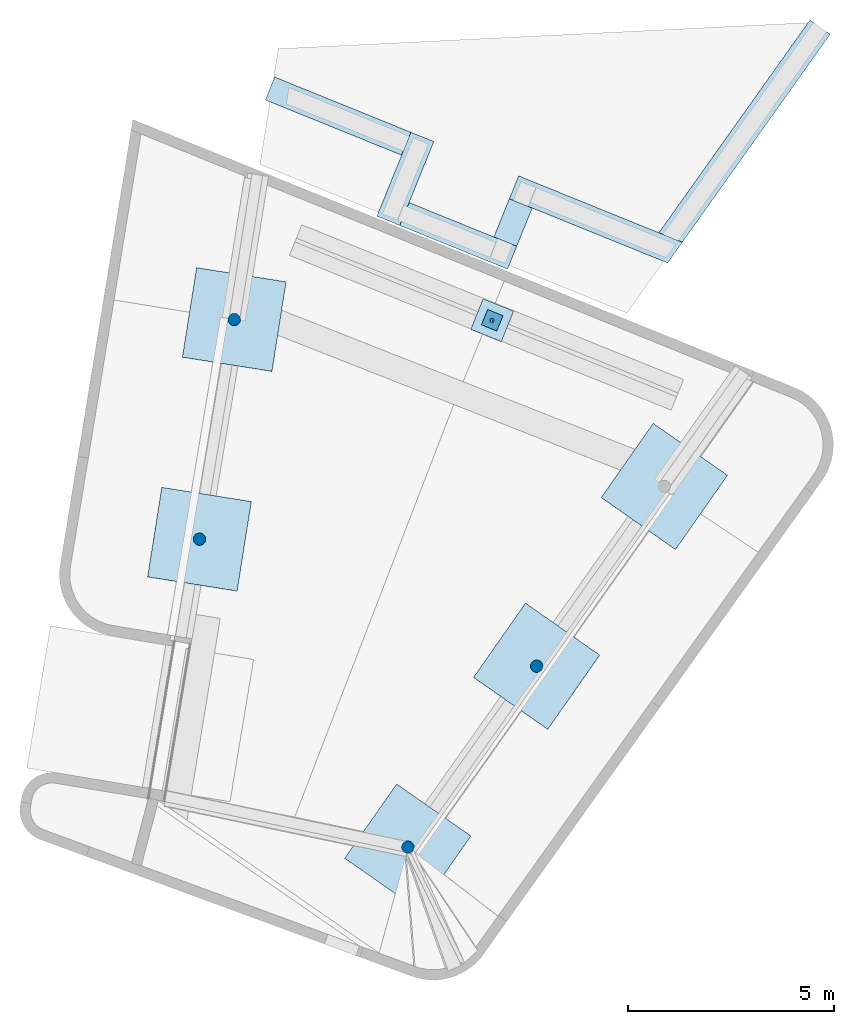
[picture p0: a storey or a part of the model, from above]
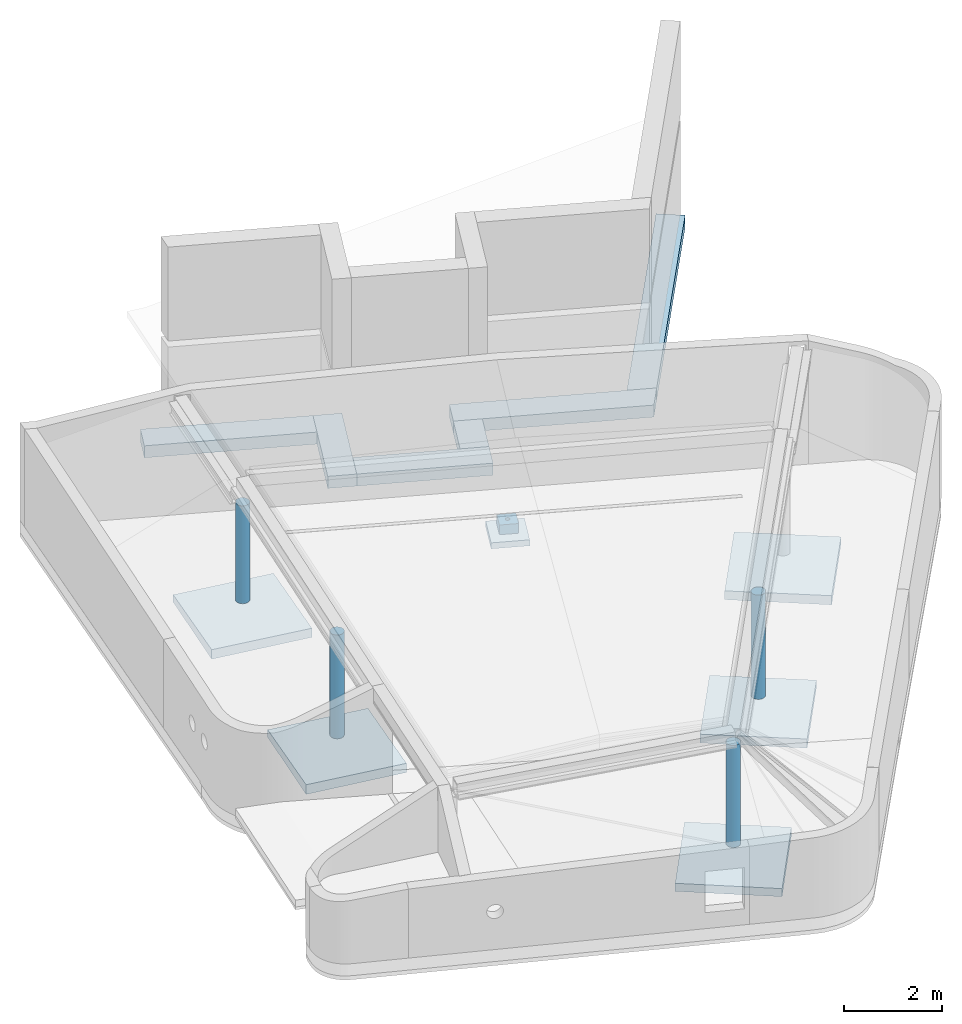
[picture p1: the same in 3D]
Properties of the parts of a building model (IFC2X3), part 1 of 2

# File
Description: ViewDefinition[CoordinationView_V2.0, QuantityTakeOffAddOnView], ExchangeRequirement[Structural, SurfaceGeometry]
File name: CC2.ifc
Time: 2018-02-07T09:57:03
Author: AAJ0\hia
Organization: Structural Designer
Written by: IFC Database Version:Work
Made in: Tekla Structures 2016i Service Pack 6, IFC Export Version: 4.0.0.0 Sep 13 2017

# IfcSite, Site
RefElevation: 0 mm

# IfcBuildingStorey, Undefined
In: Undefined
Elevation: 0 mm

# IfcBeam: 100*100 (2)
In: Undefined
Description: 100*100; Material: CONCRETE/C55/67
Aaj Tagger - Aaj_ObjektStatus: Nytt/ New; sets with these values: 2
Tekla Common - Part mark: Concrete_PLB-1-0(?); Assembly mark: PLB-0(?); Phase: 1; Class: 230; Grade: C55/67; Profile: 100*100; Name: SLUKRENNE; sets with these values: 2
Tekla Quantity - Height: 100 mm; Width: 100 mm; sets with these values: 2
Name | Center of gravity Z (mm) | Center of gravity Y (mm) | Center of gravity X (mm) | Bottom elevation | Top elevation | Net weight (kg) = Gross weight (kg) = Weight (kg) = NetWeight (kg) | Net volume (m3) = Gross volume (m3) | Gross footprint area (m2) | Area per tons (m2) | Net surface area (m2) = Gross area (m2) = OuterSurfaceArea (m2) | Tekla Quantity, Length (mm) = BaseQuantities, Length (mm) | NetVolume (m3)
SLUKRENNE | 36990.3 | 43951.6 | 41374.9 | +36.940 | +37.040 | 83.9938 | 0.035 | 349974 | 16904780 | 1.4199 | 3499.74 | 0.0349974
SLUKRENNE | 36539.9 | 53718.3 | 48906.5 | +36.490 | +36.590 | 240 | 0.1 | 1000000 | 16750000 | 4.02 | 10000 | 0.1

# IfcBeam: 100*800, PLASSTØPTFUNDAMENT
In: Undefined
Description: 100*800; Material: CONCRETE/C45/55
Tekla Common - Center of gravity Z: 36249.9 mm; Center of gravity Y: 53718.3 mm; Center of gravity X: 48906.5 mm; Bottom elevation: +36.200; Top elevation: +36.300; Part mark: Concrete_PLF-1-0(?); Assembly mark: PLF-0(?); Phase: 1; Class: 210; Grade: C45/55; Profile: 100*800; Name: PLASSTØPTFUNDAMENT; sets with these values: 2
Tekla Quantity - Net weight: 1920 kg; Gross weight: 1920 kg; Weight: 1920 kg; Net volume: 0.8 m3; Gross volume: 0.8 m3; Gross footprint area: 7999999 m2; Area per tons: 9458333 m2; Net surface area: 18.16 m2; Gross area: 18.16 m2; Height: 100 mm; Width: 800 mm; Length: 10000 mm; sets with these values: 2
Aaj Tagger - Aaj_ObjektStatus: Nytt/ New; sets with these values: 2
BaseQuantities - Length: 10000 mm; OuterSurfaceArea: 18.16 m2; NetVolume: 0.8 m3; NetWeight: 1920 kg

# IfcBeam: 200*1200, PLASSTØPTFUNDAMENT
In: Undefined
Description: 200*1200; Material: CONCRETE/C45/55
Tekla Common - Center of gravity Z: 36450 mm; Center of gravity Y: 43942.7 mm; Center of gravity X: 41428.1 mm; Bottom elevation: +36.350; Top elevation: +36.550; Part mark: Concrete_PLF-1-0(?); Assembly mark: PLF-0(?); Phase: 1; Class: 210; Grade: C45/55; Profile: 200*1200; Name: PLASSTØPTFUNDAMENT; sets with these values: 2
Tekla Quantity - Net weight: 2995.71 kg; Gross weight: 2995.71 kg; Weight: 2995.71 kg; Net volume: 1.24821 m3; Gross volume: 1.24821 m3; Gross footprint area: 6241064 m2; Area per tons: 5021340 m2; Net surface area: 15.0425 m2; Gross area: 15.0425 m2; Height: 200 mm; Width: 1200 mm; Length: 5200.89 mm; sets with these values: 2
Aaj Tagger - Aaj_Undersortering: BJELKE; Aaj_ObjektStatus: Nytt/ New; sets with these values: 2
BaseQuantities - Length: 5200.89 mm; OuterSurfaceArea: 15.0425 m2; NetVolume: 1.24821 m3; NetWeight: 2995.71 kg

# IfcBeam: HSQ305*6-30*250-15*550 (2)
In: Undefined
Description: HSQ305*6-30*250-15*550; Material: STEEL/S355
Aaj Tagger - Aaj_ObjektStatus: Nytt/ New; sets with these values: 2
Tekla Common - Center of gravity Z: 39252.6 mm; Bottom elevation: +39.100; Top elevation: +39.420; Phase: 1; Class: 330; Grade: S355; Profile: HSQ305*6-30*250-15*550; Name: STÅLBJELKE; sets with these values: 2
Tekla Quantity - Height: 320 mm; Width: 550 mm; sets with these values: 2
Name | Center of gravity Y (mm) | Center of gravity X (mm) | Part mark | Assembly mark | Net weight (kg) = Gross weight (kg) = Weight (kg) = NetWeight (kg) | Net volume (m3) = Gross volume (m3) | Gross footprint area (m2) | Area per tons (m2) | Net surface area (m2) = Gross area (m2) = OuterSurfaceArea (m2) | Tekla Quantity, Length (mm) = BaseQuantities, Length (mm) | NetVolume (m3)
STÅLBJELKE | 51008.8 | 54187.5 | DSB-3(?) | SB-3(?) | 515.938 | 0.06572 | 887164 | 18386113 | 9.4861 | 3386.12 | 0.0657246
STÅLBJELKE | 55426.6 | 43063.1 | DSB-1(?) | SB-1(?) | 542.542 | 0.06911 | 932909 | 18382423 | 9.97323 | 3560.72 | 0.0691136

# IfcBeam: HSQ305*6-40*250-20*390-12, STÅLBJELKE
In: Undefined
Description: HSQ305*6-40*250-20*390-12; Material: STEEL/S355
Aaj Tagger - Aaj_ObjektStatus: Nytt/ New; sets with these values: 2
Tekla Common - Center of gravity Z: 39575.2 mm; Center of gravity Y: 41457.4 mm; Center of gravity X: 44056.4 mm; Bottom elevation: +39.400; Top elevation: +39.725; Part mark: DSB-5(?); Assembly mark: SB-5(?); Phase: 1; Class: 330; Grade: S355; Profile: HSQ305*6-40*250-20*390-12; Name: STÅLBJELKE; sets with these values: 2
Tekla Quantity - Net weight: 1010.7 kg; Gross weight: 1010.7 kg; Weight: 1010.7 kg; Net volume: 0.12875 m3; Gross volume: 0.12875 m3; Gross footprint area: 1571900 m2; Area per tons: 14645252 m2; Net surface area: 14.802 m2; Gross area: 14.802 m2; Height: 325 mm; Width: 390 mm; Length: 5999.62 mm; sets with these values: 2
BaseQuantities - Length: 5999.62 mm; OuterSurfaceArea: 14.802 m2; NetVolume: 0.128752 m3; NetWeight: 1010.7 kg

# IfcBeam: HSQ305*6-40*250-20*550 (2)
In: Undefined
Description: HSQ305*6-40*250-20*550; Material: STEEL/S355
Aaj Tagger - Aaj_ObjektStatus: Nytt/ New; sets with these values: 2
Tekla Common - Center of gravity Z: 39553.7 mm; Bottom elevation: +39.400; Top elevation: +39.725; Phase: 1; Class: 330; Grade: S355; Profile: HSQ305*6-40*250-20*550; Name: STÅLBJELKE; sets with these values: 2
Tekla Quantity - Height: 325 mm; Width: 550 mm; sets with these values: 2
Name | Center of gravity Y (mm) | Center of gravity X (mm) | Part mark | Assembly mark | Net weight (kg) = Gross weight (kg) = Weight (kg) = NetWeight (kg) | Net volume (m3) = Gross volume (m3) | Gross footprint area (m2) | Area per tons (m2) | Net surface area (m2) = Gross area (m2) | Tekla Quantity, Length (mm) = BaseQuantities, Length (mm) | OuterSurfaceArea (m2) | NetVolume (m3)
STÅLBJELKE | 45244.7 | 50100.8 | DSB-4(?) | SB-4(?) | 2080.12 | 0.26498 | 2815309 | 14384624 | 29.9217 | 10745.5 | 29.9217 | 0.264983
STÅLBJELKE | 49752.5 | 42124.7 | DSB-2(?) | SB-2(?) | 1537.38 | 0.19584 | 2080745 | 14392994 | 22.1274 | 7941.77 | 22.1275 | 0.195844

# IfcBeam: HSQ305*6-40*250-25*390-15, STÅLBJELKE
In: Undefined
Description: HSQ305*6-40*250-25*390-15; Material: STEEL/S355
Aaj Tagger - Aaj_ObjektStatus: Nytt/ New; sets with these values: 2
Tekla Common - Center of gravity Z: 39565.4 mm; Center of gravity Y: 43922.1 mm; Center of gravity X: 41169.1 mm; Bottom elevation: +39.400; Top elevation: +39.730; Part mark: DSB-6(?); Assembly mark: SB-6(?); Phase: 1; Class: 330; Grade: S355; Profile: HSQ305*6-40*250-25*390-15; Name: STÅLBJELKE; sets with these values: 2
Tekla Quantity - Net weight: 712.152 kg; Gross weight: 712.152 kg; Weight: 712.152 kg; Net volume: 0.09072 m3; Gross volume: 0.09072 m3; Gross footprint area: 1015319 m2; Area per tons: 13506568 m2; Net surface area: 9.61873 m2; Gross area: 9.61873 m2; Height: 330 mm; Width: 390 mm; Length: 3875.27 mm; sets with these values: 2
BaseQuantities - Length: 3875.27 mm; OuterSurfaceArea: 9.61873 m2; NetVolume: 0.09072 m3; NetWeight: 712.152 kg

# IfcBeam: RHS100*4, STÅLBJELKE
In: Undefined
Description: RHS100*4; Material: STEEL/S355
Aaj Tagger - Aaj_ObjektStatus: Nytt/ New; sets with these values: 2
Tekla Common - Center of gravity Z: 39470 mm; Center of gravity Y: 49785.7 mm; Center of gravity X: 41927.3 mm; Bottom elevation: +39.420; Top elevation: +39.520; Part mark: DSB-8(?); Assembly mark: SB-8(?); Phase: 1; Class: 330; Grade: S355; Profile: RHS100*4; Name: STÅLBJELKE; sets with these values: 2
Tekla Quantity - Net weight: 95.7589 kg; Gross weight: 95.3849 kg; Weight: 95.3849 kg; Net volume: 0.0122 m3; Gross volume: 0.01215 m3; Gross footprint area: 794179 m2; Area per tons: 32554848 m2; Net surface area: 3.17832 m2; Gross area: 3.10524 m2; Height: 100 mm; Width: 100 mm; Length: 7941.79 mm; sets with these values: 2
BaseQuantities - Length: 7941.79 mm; OuterSurfaceArea: 3.10524 m2; NetVolume: 0.0121986 m3; NetWeight: 95.7589 kg

# IfcBeam: RHS100*5 (4)
In: Undefined
Description: RHS100*5; Material: STEEL/S355
Aaj Tagger - Aaj_ObjektStatus: Nytt/ New; sets with these values: 2
Tekla Common - Phase: 1; Class: 330; Grade: S355; Profile: RHS100*5; Name: STÅLBJELKE; sets with these values: 2
Tekla Quantity - Area per tons: 26219122 m2; Height: 100 mm; Width: 100 mm; sets with these values: 2
Name | Center of gravity Z (mm) | Center of gravity Y (mm) | Center of gravity X (mm) | Bottom elevation | Top elevation | Part mark | Assembly mark | Net weight (kg) = NetWeight (kg) | Gross weight (kg) = Weight (kg) | Net volume (m3) | Gross volume (m3) | Gross footprint area (m2) | Net surface area (m2) | Gross area (m2) = OuterSurfaceArea (m2) | Tekla Quantity, Length (mm) = BaseQuantities, Length (mm) | NetVolume (m3)
STÅLBJELKE | 39470 | 45140.1 | 50248.5 | +39.420 | +39.520 | DSB-0(?) | SB-0(?) | 160.268 | 159.425 | 0.02042 | 0.02031 | 1074546 | 4.30018 | 4.17998 | 10745.5 | 0.0204164
STÅLBJELKE | 39165 | 50857.4 | 54301.7 | +39.115 | +39.215 | DSB-0(?) | SB-0(?) | 48.8032 | 48.5464 | 0.00622 | 0.00618 | 327209 | 1.31084 | 1.27284 | 3272.09 | 0.00621697
STÅLBJELKE | 39165 | 55455 | 42884.3 | +39.115 | +39.215 | DSB-0(?) | SB-0(?) | 53.1082 | 52.8287 | 0.00677 | 0.00673 | 356072 | 1.42629 | 1.38512 | 3560.72 | 0.00676537
STÅLBJELKE | 39470 | 41298.8 | 44023.1 | +39.420 | +39.520 | DSB-7(?) | SB-7(?) | 89.4844 | 89.0134 | 0.0114 | 0.01134 | 599962 | 2.40185 | 2.33385 | 5999.62 | 0.0113993

# IfcBeam: TRIANGLE300*600, PLASSTØPTBJELKE
In: Undefined
Description: TRIANGLE300*600; Material: CONCRETE/C55/67
Aaj Tagger - Aaj_ObjektStatus: Nytt/ New; sets with these values: 2
Tekla Common - Center of gravity Z: 39540 mm; Center of gravity Y: 51837.8 mm; Center of gravity X: 48063.4 mm; Bottom elevation: +39.440; Top elevation: +39.740; Part mark: Concrete_PLB-1-0(?); Assembly mark: PLB-0(?); Phase: 1; Class: 230; Grade: C55/67; Profile: TRIANGLE300*600; Name: PLASSTØPTBJELKE; sets with these values: 2
Tekla Quantity - Net weight: 2348.64 kg; Gross weight: 2348.64 kg; Weight: 2348.64 kg; Net volume: 0.9786 m3; Gross volume: 0.9786 m3; Gross footprint area: 0 m2; Area per tons: 7348957 m2; Net surface area: 17.26 m2; Gross area: 17.26 m2; Height: 300 mm; Width: 600 mm; Length: 10873.3 mm; sets with these values: 2
BaseQuantities - Length: 10873.3 mm; OuterSurfaceArea: 17.26 m2; NetVolume: 0.978599 m3; NetWeight: 2348.64 kg

# IfcColumn: D300 (5)
In: Undefined
Description: D300; Material: CONCRETE/C55/67
Aaj Tagger - Aaj_ObjektStatus: Nytt/ New; sets with these values: 2
Tekla Common - Part mark: Concrete_PLS-1-3(?); Assembly mark: PLS-0(?); Phase: 1; Class: 220; Grade: C55/67; Profile: D300; Name: PLASSTØPTSØYLE; sets with these values: 2
Tekla Quantity - Gross footprint area: 70232.5 m2; Height: 300 mm; Width: 300 mm; sets with these values: 2
Name | Center of gravity Z (mm) | Center of gravity Y (mm) | Center of gravity X (mm) | Bottom elevation | Top elevation | Net weight (kg) = Gross weight (kg) = Weight (kg) | Net volume (m3) = Gross volume (m3) | Area per tons (m2) | Net surface area (m2) = Gross area (m2) = OuterSurfaceArea (m2) | Tekla Quantity, Length (mm) = BaseQuantities, Length (mm) | NetVolume (m3) | NetWeight (kg)
PLASSTØPTSØYLE | 38103.4 | 48334.8 | 41938.7 | +36.807 | +39.400 | 437.089 | 0.18212 | 5903801 | 2.58049 | 2593.11 | 0.18212 | 437.089
PLASSTØPTSØYLE | 37876.3 | 53668.3 | 42783.5 | +36.653 | +39.100 | 412.517 | 0.17188 | 5922944 | 2.44331 | 2447.33 | 0.171882 | 412.516
PLASSTØPTSØYLE | 37873.5 | 49616.1 | 53224.5 | +36.647 | +39.100 | 413.477 | 0.17228 | 5922153 | 2.44868 | 2453.03 | 0.172282 | 413.477
PLASSTØPTSØYLE | 38097.6 | 45251.2 | 50123.7 | +36.795 | +39.400 | 439.063 | 0.18294 | 5902357 | 2.59151 | 2604.82 | 0.182943 | 439.063
PLASSTØPTSØYLE | 38125 | 40859.8 | 46996.1 | +36.850 | +39.400 | 429.823 | 0.17909 | 5909234 | 2.53992 | 2550 | 0.179093 | 429.823

# IfcFooting: 2200*2200 (5)
In: Undefined
Description: 2200*2200; Material: CONCRETE/C45/55
Tekla Common - Part mark: Concrete_PLF-1-19(?); Assembly mark: PLF-0(?); Phase: 1; Class: 210; Grade: C45/55; Profile: 2200*2200; Name: PLASSTØPTFUNDAMENT; sets with these values: 2
Tekla Quantity - Height: 2200 mm; Width: 2200 mm; sets with these values: 2
Aaj Tagger - Aaj_Undersortering: PUNKT; Aaj_ObjektStatus: Nytt/ New; sets with these values: 2
BaseQuantities - CrossSectionArea: 4.84 m2; Width: 2200 mm; Height: 2200 mm
Name | Center of gravity Z (mm) | Center of gravity Y (mm) | Center of gravity X (mm) | Bottom elevation | Top elevation | Net weight (kg) = Weight (kg) = NetWeight (kg) | Gross weight (kg) = GrossWeight (kg) | Net volume (m3) | Gross volume (m3) = GrossVolume (m3) | Gross footprint area (m2) | Area per tons (m2) | Net surface area (m2) = OuterSurfaceArea (m2) | Gross area (m2) = GrossSurfaceArea (m2) | Tekla Quantity, Length (mm) = BaseQuantities, Length (mm) | NetVolume (m3)
PLASSTØPTFUNDAMENT | 36404.9 | 48293.4 | 41920.9 | +36.293 | +36.546 | 2419.97 | 2775.32 | 1.00832 | 1.20992 | 0 | 4757766 | 11.5137 | 11.8799 | 238.922 | 1.00832
PLASSTØPTFUNDAMENT | 36253.2 | 53624.4 | 42765.7 | +36.143 | +36.393 | 2378.67 | 2740.99 | 0.99111 | 1.20992 | 0 | 4827637 | 11.4834 | 11.8799 | 235.966 | 0.991114
PLASSTØPTFUNDAMENT | 36249.8 | 49572.8 | 53205.6 | +36.143 | +36.385 | 2300.02 | 2642.24 | 0.95834 | 1.20992 | 0 | 4966780 | 11.4237 | 11.8799 | 227.465 | 0.958341
PLASSTØPTFUNDAMENT | 36450 | 40859.8 | 46996.1 | +36.350 | +36.550 | 2323.2 | 2323.2 | 0.968 | 0.968 | 4840000 | 4924242 | 11.44 | 11.44 | 200 | 0.968
PLASSTØPTFUNDAMENT | 36399.2 | 45207.8 | 50104.7 | +36.293 | +36.534 | 2286.67 | 2628.88 | 0.95278 | 1.20992 | 0 | 4991359 | 11.4136 | 11.8799 | 226.316 | 0.952778

# IfcFooting: 300*600 (6)
In: Undefined
Description: 300*600; Material: CONCRETE/B35
Tekla Common - Center of gravity Z: 36850 mm; Bottom elevation: +36.700; Top elevation: +37.000; Assembly mark: PLF-2; Phase: 1; Class: 210; Grade: B35; Profile: 300*600; Name: PLASSTØPTFUNDAMENT; sets with these values: 2
Tekla Quantity - Height: 300 mm; Width: 600 mm; sets with these values: 2
Aaj Tagger - Aaj_Undersortering: STRIPE; Aaj_ObjektStatus: Eksisterende/ Existing; sets with these values: 2
BaseQuantities - CrossSectionArea: 0.18 m2; Width: 600 mm; Height: 300 mm
Name | Center of gravity Y (mm) | Center of gravity X (mm) | Part mark | Net weight (kg) = Weight (kg) = NetWeight (kg) | Gross weight (kg) = GrossWeight (kg) | Net volume (m3) = Gross volume (m3) | Gross footprint area (m2) | Area per tons (m2) | Net surface area (m2) = Gross area (m2) = OuterSurfaceArea (m2) = GrossSurfaceArea (m2) | Tekla Quantity, Length (mm) = BaseQuantities, Length (mm) | NetVolume (m3) = GrossVolume (m3)
PLASSTØPTFUNDAMENT | 56022.9 | 49551 | Concrete_PLF-1-6 | 432.04 | 432.1 | 0.18002 | 600056 | 4999923 | 2.16017 | 1000.23 | 0.180017
PLASSTØPTFUNDAMENT | 55698.5 | 48221.9 | Concrete_PLF-1-5 | 1218.32 | 1218.41 | 0.50764 | 1692117 | 4462155 | 5.43635 | 2820.39 | 0.507635
PLASSTØPTFUNDAMENT | 57081.7 | 46937.1 | Concrete_PLF-1-4 | 949.61 | 949.7 | 0.39567 | 1318903 | 4545770 | 4.31671 | 2198.38 | 0.395671
PLASSTØPTFUNDAMENT | 58605.9 | 45305.1 | Concrete_PLF-1-3 | 1542.18 | 1542.23 | 0.64258 | 2141919 | 4400102 | 6.78576 | 3569.98 | 0.642576
PLASSTØPTFUNDAMENT | 58213.1 | 55189.6 | Concrete_PLF-1-2 | 2706.08 | 2736.81 | 1.12754 | 3758451 | 4301544 | 11.6403 | 6335.2 | 1.12754
PLASSTØPTFUNDAMENT | 56086.2 | 51529.2 | Concrete_PLF-1-7 | 1822.63 | 1853.37 | 0.75943 | 2531426 | 4366921 | 7.95927 | 4290.2 | 0.759428

# IfcFooting: 400*400, OLJEUTSKILLER
In: Undefined
Description: 400*400; Material: CONCRETE/C45/55
Tekla Common - Center of gravity Z: 36368.2 mm; Center of gravity Y: 53649.1 mm; Center of gravity X: 49044.3 mm; Bottom elevation: +36.249; Top elevation: +36.492; Part mark: Concrete_PLF-1-1(?); Assembly mark: PLF-0(?); Phase: 1; Class: 210; Grade: C45/55; Profile: 400*400; Name: OLJEUTSKILLER; sets with these values: 2
Tekla Quantity - Net weight: 86.3647 kg; Gross weight: 92.6545 kg; Weight: 86.3647 kg; Net volume: 0.03599 m3; Gross volume: 0.04 m3; Gross footprint area: 0 m2; Area per tons: 8850370 m2; Net surface area: 0.76436 m2; Gross area: 0.71997 m2; Height: 400 mm; Width: 400 mm; Length: 241.288 mm; sets with these values: 2
Aaj Tagger - Aaj_Undersortering: PUNKT; Aaj_Delmengde: OLJEUTSKILLER; Aaj_ObjektStatus: Nytt/ New; sets with these values: 2
BaseQuantities - Length: 241.288 mm; OuterSurfaceArea: 0.76436 m2; GrossSurfaceArea: 0.719974 m2; CrossSectionArea: 0.16 m2; NetVolume: 0.0359853 m3; GrossVolume: 0.0399974 m3; NetWeight: 86.3647 kg; GrossWeight: 92.6545 kg; Width: 400 mm; Height: 400 mm

# IfcFooting: 800*800, PLASSTØPTFUNDAMENT
In: Undefined
Description: 800*800; Material: CONCRETE/C45/55
Aaj Tagger - Aaj_Undersortering: PUNKT; Aaj_Delmengde: OLJEUTSKILLER; Aaj_ObjektStatus: Nytt/ New; sets with these values: 2
Tekla Common - Center of gravity Z: 36126 mm; Center of gravity Y: 53650.5 mm; Center of gravity X: 49044.7 mm; Bottom elevation: +36.048; Top elevation: +36.204; Part mark: Concrete_PLF-1-1(?); Assembly mark: PLF-0(?); Phase: 1; Class: 210; Grade: C45/55; Profile: 800*800; Name: PLASSTØPTFUNDAMENT; sets with these values: 2
Tekla Quantity - Net weight: 227.2 kg; Gross weight: 227.2 kg; Weight: 227.2 kg; Net volume: 0.09467 m3; Gross volume: 0.09467 m3; Gross footprint area: 0 m2; Area per tons: 7717138 m2; Net surface area: 1.75333 m2; Gross area: 1.75333 m2; Height: 800 mm; Width: 800 mm; Length: 147.917 mm; sets with these values: 2
BaseQuantities - Length: 147.917 mm; OuterSurfaceArea: 1.75333 m2; GrossSurfaceArea: 1.75333 m2; CrossSectionArea: 0.64 m2; NetVolume: 0.0946666 m3; GrossVolume: 0.0946666 m3; NetWeight: 227.2 kg; GrossWeight: 227.2 kg; Width: 800 mm; Height: 800 mm

# IfcPlate: 0.5*2664, MEMBRAN
In: Undefined
Description: 0.5*2664; Material: MISCELLANEOUS/Misc_Undefined
Aaj Tagger - Aaj_ObjektStatus: Nytt/ New; sets with these values: 2
Tekla Common - Center of gravity Z: 38973.5 mm; Center of gravity Y: 50118.3 mm; Center of gravity X: 55433.2 mm; Bottom elevation: +38.504; Top elevation: +39.422; Part mark: Concrete_IXPS-1-0(?); Assembly mark: IXPS-0(?); Phase: 1; Class: 912; Grade: Misc_Undefined; Profile: 0.5*2664; Name: MEMBRAN; sets with these values: 2
Tekla Quantity - Net weight: 0 kg; Gross weight: 0 kg; Weight: 0 kg; Net volume: 0.00453 m3; Gross volume: 0.00496 m3; Gross footprint area: 0 m2; Net surface area: 18.1338 m2; Gross area: 9.68366 m2; Height: 2663.91 mm; Width: 0.5 mm; Length: 3635.14 mm; sets with these values: 2
BaseQuantities - Width: 2663.91 mm; NetArea: 18.1338 m2; GrossArea: 9.68366 m2; CrossSectionArea: 2.5e-07 m2; NetVolume: 0.00453197 m3; GrossVolume: 0.00495974 m3

# IfcPlate: 0.5*2751, MEMBRAN
In: Undefined
Description: 0.5*2751; Material: MISCELLANEOUS/Misc_Undefined
Aaj Tagger - Aaj_ObjektStatus: Nytt/ New; sets with these values: 2
Tekla Common - Center of gravity Z: 39126.1 mm; Center of gravity Y: 44341.7 mm; Center of gravity X: 51368.5 mm; Bottom elevation: +38.524; Top elevation: +39.720; Part mark: Concrete_IXPS-1-0(?); Assembly mark: IXPS-0(?); Phase: 1; Class: 912; Grade: Misc_Undefined; Profile: 0.5*2751; Name: MEMBRAN; sets with these values: 2
Tekla Quantity - Net weight: 0 kg; Gross weight: 0 kg; Weight: 0 kg; Net volume: 0.01471 m3; Gross volume: 0.01526 m3; Gross footprint area: 0 m2; Net surface area: 58.8691 m2; Gross area: 29.8807 m2; Height: 2750.94 mm; Width: 0.5 mm; Length: 10862 mm; sets with these values: 2
BaseQuantities - Width: 2750.94 mm; NetArea: 58.8691 m2; GrossArea: 29.8808 m2; CrossSectionArea: 2.5e-07 m2; NetVolume: 0.0147137 m3; GrossVolume: 0.0152558 m3

# IfcPlate: 0.5*2815, MEMBRAN
In: Undefined
Description: 0.5*2815; Material: MISCELLANEOUS/Misc_Undefined
Aaj Tagger - Aaj_ObjektStatus: Nytt/ New; sets with these values: 2
Tekla Common - Center of gravity Z: 38944 mm; Center of gravity Y: 55804 mm; Center of gravity X: 41442.6 mm; Bottom elevation: +38.495; Top elevation: +39.415; Part mark: Concrete_IXPS-1-0(?); Assembly mark: IXPS-0(?); Phase: 1; Class: 912; Grade: Misc_Undefined; Profile: 0.5*2815; Name: MEMBRAN; sets with these values: 2
Tekla Quantity - Net weight: 0 kg; Gross weight: 0 kg; Weight: 0 kg; Net volume: 0.00531 m3; Gross volume: 0.00574 m3; Gross footprint area: 0 m2; Net surface area: 21.252 m2; Gross area: 11.5174 m2; Height: 2814.62 mm; Width: 0.5 mm; Length: 4092 mm; sets with these values: 2
BaseQuantities - Width: 2814.62 mm; NetArea: 21.252 m2; GrossArea: 11.5174 m2; CrossSectionArea: 2.5e-07 m2; NetVolume: 0.00531136 m3; GrossVolume: 0.00573829 m3

# IfcPlate: 0.5*2953, MEMBRAN
In: Undefined
Description: 0.5*2953; Material: MISCELLANEOUS/Misc_Undefined
Aaj Tagger - Aaj_ObjektStatus: Nytt/ New; sets with these values: 2
Tekla Common - Center of gravity Z: 39117.5 mm; Center of gravity Y: 50134.2 mm; Center of gravity X: 40514.8 mm; Bottom elevation: +38.493; Top elevation: +39.726; Part mark: Concrete_IXPS-1-0(?); Assembly mark: IXPS-0(?); Phase: 1; Class: 912; Grade: Misc_Undefined; Profile: 0.5*2953; Name: MEMBRAN; sets with these values: 2
Tekla Quantity - Net weight: 0 kg; Gross weight: 0 kg; Weight: 0 kg; Net volume: 0.01128 m3; Gross volume: 0.01155 m3; Gross footprint area: 0 m2; Net surface area: 45.1327 m2; Gross area: 23.0887 m2; Height: 2952.85 mm; Width: 0.5 mm; Length: 7819.12 mm; sets with these values: 2
BaseQuantities - Width: 2952.85 mm; NetArea: 45.1327 m2; GrossArea: 23.0887 m2; CrossSectionArea: 2.5e-07 m2; NetVolume: 0.0112806 m3; GrossVolume: 0.0115528 m3

# IfcPlate: 0.5*3189, MEMBRAN
In: Undefined
Description: 0.5*3189; Material: MISCELLANEOUS/Misc_Undefined
Aaj Tagger - Aaj_ObjektStatus: Nytt/ New; sets with these values: 2
Tekla Common - Center of gravity Z: 39514.2 mm; Center of gravity Y: 52178.1 mm; Center of gravity X: 51403.6 mm; Bottom elevation: +39.440; Top elevation: +39.591; Part mark: Concrete_IXPS-1-4(?); Assembly mark: IXPS-4(?); Phase: 1; Class: 912; Grade: Misc_Undefined; Profile: 0.5*3189; Name: MEMBRAN; sets with these values: 2
Tekla Quantity - Net weight: 0 kg; Gross weight: 0 kg; Weight: 0 kg; Net volume: 0.00856 m3; Gross volume: 0.00912 m3; Gross footprint area: 0 m2; Net surface area: 34.2758 m2; Gross area: 19.3506 m2; Height: 3189.15 mm; Width: 150.5 mm; Length: 6067.64 mm; sets with these values: 2
BaseQuantities - Width: 3189.15 mm; NetArea: 34.2758 m2; GrossArea: 19.3506 m2; CrossSectionArea: 2.5e-07 m2; NetVolume: 0.0085634 m3; GrossVolume: 0.00912207 m3

# IfcPlate: 0.5*3290, MEMBRAN
In: Undefined
Description: 0.5*3290; Material: MISCELLANEOUS/Misc_Undefined
Aaj Tagger - Aaj_ObjektStatus: Nytt/ New; sets with these values: 2
Tekla Common - Center of gravity Z: 39517.2 mm; Center of gravity Y: 54333.9 mm; Center of gravity X: 46005.7 mm; Bottom elevation: +39.440; Top elevation: +39.591; Part mark: Concrete_IXPS-1-6(?); Assembly mark: IXPS-6(?); Phase: 1; Class: 912; Grade: Misc_Undefined; Profile: 0.5*3290; Name: MEMBRAN; sets with these values: 2
Tekla Quantity - Net weight: 0 kg; Gross weight: 0 kg; Weight: 0 kg; Net volume: 0.00914 m3; Gross volume: 0.00972 m3; Gross footprint area: 0 m2; Net surface area: 36.5751 m2; Gross area: 20.8552 m2; Height: 3290.31 mm; Width: 150.5 mm; Length: 6338.36 mm; sets with these values: 2
BaseQuantities - Width: 3290.31 mm; NetArea: 36.5751 m2; GrossArea: 20.8552 m2; CrossSectionArea: 2.5e-07 m2; NetVolume: 0.00913822 m3; GrossVolume: 0.00971979 m3

# IfcPlate: 0.5*5306, MEMBRAN
In: Undefined
Description: 0.5*5306; Material: MISCELLANEOUS/Misc_Undefined
Aaj Tagger - Aaj_ObjektStatus: Nytt/ New; sets with these values: 2
Tekla Common - Center of gravity Z: 39815.3 mm; Center of gravity Y: 45985.2 mm; Center of gravity X: 48093 mm; Bottom elevation: +39.740; Top elevation: +39.890; Part mark: Concrete_IXPS-1-5(?); Assembly mark: IXPS-5(?); Phase: 1; Class: 912; Grade: Misc_Undefined; Profile: 0.5*5306; Name: MEMBRAN; sets with these values: 2
Tekla Quantity - Net weight: 0 kg; Gross weight: 0 kg; Weight: 0 kg; Net volume: 0.71928 m3; Gross volume: 0.71928 m3; Gross footprint area: 0 m2; Net surface area: 83.6087 m2; Gross area: 56.9467 m2; Height: 5305.71 mm; Width: 150.5 mm; Length: 10733.1 mm; sets with these values: 2
BaseQuantities - Width: 5305.71 mm; NetArea: 83.6087 m2; GrossArea: 56.9467 m2; CrossSectionArea: 2.5e-07 m2; NetVolume: 0.719278 m3; GrossVolume: 0.719278 m3

# IfcPlate: 0.5*5446, MEMBRAN
In: Undefined
Description: 0.5*5446; Material: MISCELLANEOUS/Misc_Undefined
Aaj Tagger - Aaj_ObjektStatus: Nytt/ New; sets with these values: 2
Tekla Common - Center of gravity Z: 39808.1 mm; Center of gravity Y: 47730.4 mm; Center of gravity X: 44178.2 mm; Bottom elevation: +39.740; Top elevation: +39.890; Part mark: Concrete_IXPS-1-5(?); Assembly mark: IXPS-0(?); Phase: 1; Class: 912; Grade: Misc_Undefined; Profile: 0.5*5446; Name: MEMBRAN; sets with these values: 2
Tekla Quantity - Net weight: 0 kg; Gross weight: 0 kg; Weight: 0 kg; Net volume: 0.02446 m3; Gross volume: 0.02446 m3; Gross footprint area: 0 m2; Net surface area: 97.8982 m2; Gross area: 63.5609 m2; Height: 5446.06 mm; Width: 150.5 mm; Length: 11671 mm; sets with these values: 2
BaseQuantities - Width: 5446.06 mm; NetArea: 97.8982 m2; GrossArea: 63.5609 m2; CrossSectionArea: 2.5e-07 m2; NetVolume: 0.0244554 m3; GrossVolume: 0.0244554 m3

# IfcPlate: 100*10545, ISOLASJON
In: Undefined
Description: 100*10545; Material: MISCELLANEOUS/XPS
Aaj Tagger - Aaj_ObjektStatus: Nytt/ New; sets with these values: 2
Tekla Common - Center of gravity Z: 36341.8 mm; Center of gravity Y: 50311.5 mm; Center of gravity X: 47405.4 mm; Bottom elevation: +36.150; Top elevation: +36.550; Part mark: Concrete_PLD-1-0(?); Assembly mark: PLD-0(?); Phase: 1; Class: 912; Grade: XPS; Profile: 100*10545; Name: ISOLASJON; sets with these values: 2
Tekla Quantity - Net weight: 431.282 kg; Gross weight: 496.509 kg; Weight: 431.282 kg; Net volume: 17.2513 m3; Gross volume: 17.2513 m3; Gross footprint area: 0 m2; Area per tons: 818902108 m2; Net surface area: 353.178 m2; Gross area: 198.604 m2; Height: 10545.4 mm; Width: 400 mm; Length: 18833.2 mm; sets with these values: 2
BaseQuantities - Width: 10545.4 mm; NetArea: 353.178 m2; GrossArea: 198.604 m2; CrossSectionArea: 0.01 m2; NetVolume: 17.2513 m3; GrossVolume: 17.2513 m3

# IfcPlate: 100*3237, VEKSTLAG
In: Undefined
Description: 100*3237; Material: MISCELLANEOUS/Misc_Undefined
Aaj Tagger - Aaj_ObjektStatus: Nytt/ New; sets with these values: 2
Tekla Common - Center of gravity Z: 39663.5 mm; Center of gravity Y: 52083.1 mm; Center of gravity X: 51372.4 mm; Bottom elevation: +39.540; Top elevation: +39.790; Part mark: Concrete_IXPS-1-4(?); Assembly mark: IXPS-0(?); Phase: 1; Class: 911; Grade: Misc_Undefined; Profile: 100*3237; Name: VEKSTLAG; sets with these values: 2
Tekla Quantity - Net weight: 0 kg; Gross weight: 0 kg; Weight: 0 kg; Net volume: 1.82441 m3; Gross volume: 1.82441 m3; Gross footprint area: 0 m2; Net surface area: 38.2892 m2; Gross area: 19.6455 m2; Height: 3237.45 mm; Width: 250 mm; Length: 6068.19 mm; sets with these values: 2
BaseQuantities - Width: 3237.45 mm; NetArea: 38.2892 m2; GrossArea: 19.6455 m2; CrossSectionArea: 0.01 m2; NetVolume: 1.82441 m3; GrossVolume: 1.82441 m3

# IfcPlate: 100*3290, VEKSTLAG
In: Undefined
Description: 100*3290; Material: MISCELLANEOUS/Misc_Undefined
Aaj Tagger - Aaj_ObjektStatus: Nytt/ New; sets with these values: 2
Tekla Common - Center of gravity Z: 39666.4 mm; Center of gravity Y: 54244.3 mm; Center of gravity X: 45962 mm; Bottom elevation: +39.540; Top elevation: +39.790; Part mark: Concrete_IXPS-1-6(?); Assembly mark: IXPS-0(?); Phase: 1; Class: 911; Grade: Misc_Undefined; Profile: 100*3290; Name: VEKSTLAG; sets with these values: 2
Tekla Quantity - Net weight: 0 kg; Gross weight: 0 kg; Weight: 0 kg; Net volume: 1.94396 m3; Gross volume: 1.94396 m3; Gross footprint area: 0 m2; Net surface area: 40.744 m2; Gross area: 20.8552 m2; Height: 3290.31 mm; Width: 250 mm; Length: 6338.36 mm; sets with these values: 2
BaseQuantities - Width: 3290.31 mm; NetArea: 40.744 m2; GrossArea: 20.8552 m2; CrossSectionArea: 0.01 m2; NetVolume: 1.94396 m3; GrossVolume: 1.94396 m3

# IfcPlate: 100*3443, ISOLASJON
In: Undefined
Description: 100*3443; Material: MISCELLANEOUS/XPS
Aaj Tagger - Aaj_ObjektStatus: Nytt/ New; sets with these values: 2
Tekla Common - Center of gravity Z: 37087.1 mm; Center of gravity Y: 44225.6 mm; Center of gravity X: 39722.2 mm; Bottom elevation: +36.800; Top elevation: +37.330; Part mark: Concrete_PLD-1-0(?); Assembly mark: PLD-0(?); Phase: 1; Class: 912; Grade: XPS; Profile: 100*3443; Name: ISOLASJON; sets with these values: 2
Tekla Quantity - Net weight: 20.9616 kg; Gross weight: 30.1232 kg; Weight: 20.9616 kg; Net volume: 0.83846 m3; Gross volume: 4.25516 m3; Gross footprint area: 0 m2; Area per tons: 1202437501 m2; Net surface area: 25.205 m2; Gross area: 12.0493 m2; Height: 3442.76 mm; Width: 530.325 mm; Length: 3499.89 mm; sets with these values: 2
BaseQuantities - Width: 3442.76 mm; NetArea: 25.205 m2; GrossArea: 12.0493 m2; CrossSectionArea: 0.01 m2; NetVolume: 0.838463 m3; GrossVolume: 4.25516 m3

# IfcPlate: 100*5306, VEKSTLAG
In: Undefined
Description: 100*5306; Material: MISCELLANEOUS/Misc_Undefined
Aaj Tagger - Aaj_ObjektStatus: Nytt/ New; sets with these values: 2
Tekla Common - Center of gravity Z: 39965.6 mm; Center of gravity Y: 46420.4 mm; Center of gravity X: 48307.9 mm; Bottom elevation: +39.840; Top elevation: +40.090; Part mark: Concrete_IXPS-1-5(?); Assembly mark: IXPS-5(?); Phase: 1; Class: 911; Grade: Misc_Undefined; Profile: 100*5306; Name: VEKSTLAG; sets with these values: 2
Tekla Quantity - Net weight: 0 kg; Gross weight: 0 kg; Weight: 0 kg; Net volume: 4.87465 m3; Gross volume: 4.87465 m3; Gross footprint area: 0 m2; Net surface area: 86.5299 m2; Gross area: 56.9467 m2; Height: 5305.71 mm; Width: 250 mm; Length: 10733.1 mm; sets with these values: 2
BaseQuantities - Width: 5305.71 mm; NetArea: 86.5299 m2; GrossArea: 56.9467 m2; CrossSectionArea: 0.01 m2; NetVolume: 4.87465 m3; GrossVolume: 4.87465 m3

# IfcPlate: 100*5446, VEKSTLAG
In: Undefined
Description: 100*5446; Material: MISCELLANEOUS/Misc_Undefined
Aaj Tagger - Aaj_ObjektStatus: Nytt/ New; sets with these values: 2
Tekla Common - Center of gravity Z: 39957.8 mm; Center of gravity Y: 47730.4 mm; Center of gravity X: 44178.2 mm; Bottom elevation: +39.840; Top elevation: +40.090; Part mark: Concrete_IXPS-1-5(?); Assembly mark: IXPS-0(?); Phase: 1; Class: 911; Grade: Misc_Undefined; Profile: 100*5446; Name: VEKSTLAG; sets with these values: 2
Tekla Quantity - Net weight: 0 kg; Gross weight: 0 kg; Weight: 0 kg; Net volume: 4.89108 m3; Gross volume: 4.89108 m3; Gross footprint area: 0 m2; Net surface area: 100.999 m2; Gross area: 63.5609 m2; Height: 5446.06 mm; Width: 250 mm; Length: 11671 mm; sets with these values: 2
BaseQuantities - Width: 5446.06 mm; NetArea: 100.999 m2; GrossArea: 63.5609 m2; CrossSectionArea: 0.01 m2; NetVolume: 4.89108 m3; GrossVolume: 4.89108 m3

# IfcPlate: 100*6761, ISOLASJON
In: Undefined
Description: 100*6761; Material: MISCELLANEOUS/XPS
Aaj Tagger - Aaj_ObjektStatus: Nytt/ New; sets with these values: 2
Tekla Common - Center of gravity Z: 36500 mm; Center of gravity Y: 42210.3 mm; Center of gravity X: 44637.3 mm; Bottom elevation: +36.450; Top elevation: +36.550; Part mark: Concrete_PLD-1-0(?); Assembly mark: PLD-0(?); Phase: 1; Class: 912; Grade: XPS; Profile: 100*6761; Name: ISOLASJON; sets with these values: 2
Tekla Quantity - Net weight: 181.577 kg; Gross weight: 243.127 kg; Weight: 181.577 kg; Net volume: 7.26306 m3; Gross volume: 7.26306 m3; Gross footprint area: 72630605 m2; Area per tons: 823827619 m2; Net surface area: 149.588 m2; Gross area: 97.2508 m2; Height: 6761.21 mm; Width: 100 mm; Length: 14383.6 mm; sets with these values: 2
BaseQuantities - Width: 6761.21 mm; NetArea: 149.588 m2; GrossArea: 97.2508 m2; CrossSectionArea: 0.01 m2; NetVolume: 7.26306 m3; GrossVolume: 7.26306 m3

# IfcPlate: 20*390, BRANNBESKYTTELSE
In: Undefined
Description: 20*390; Material: MISCELLANEOUS/Misc_Undefined
Aaj Tagger - Aaj_ObjektStatus: Nytt/ New; sets with these values: 2
Tekla Common - Center of gravity Z: 39390 mm; Center of gravity Y: 43917.4 mm; Center of gravity X: 41197.3 mm; Bottom elevation: +39.380; Top elevation: +39.400; Part mark: DIBB-1(?); Assembly mark: IBB-1(?); Phase: 1; Class: 920; Grade: Misc_Undefined; Profile: 20*390; Name: BRANNBESKYTTELSE; sets with these values: 2
Tekla Quantity - Net weight: 0 kg; Gross weight: 0 kg; Weight: 0 kg; Net volume: 0.03023 m3; Gross volume: 0.03023 m3; Gross footprint area: 1511353 m2; Net surface area: 3.19332 m2; Gross area: 1.51135 m2; Height: 390 mm; Width: 20 mm; Length: 3875.27 mm; sets with these values: 2
BaseQuantities - Width: 390 mm; NetArea: 3.19332 m2; GrossArea: 1.51135 m2; CrossSectionArea: 0.0004 m2; NetVolume: 0.0302271 m3; GrossVolume: 0.0302271 m3

# IfcPlate: 20*45 (2)
In: Undefined
Description: 20*45; Material: MISCELLANEOUS/Misc_Undefined
Aaj Tagger - Aaj_ObjektStatus: Nytt/ New; sets with these values: 2
Tekla Common - Center of gravity Z: 39402.5 mm; Bottom elevation: +39.380; Top elevation: +39.425; Phase: 1; Class: 920; Grade: Misc_Undefined; Profile: 20*45; Name: BRANNBESKYTTELSE; sets with these values: 2
Tekla Quantity - Net weight: 0 kg; Gross weight: 0 kg; Weight: 0 kg; Net volume: 0.00349 m3; Gross volume: 0.00349 m3; Gross footprint area: 77505.3 m2; Net surface area: 0.50558 m2; Gross area: 0.17439 m2; Height: 45 mm; Width: 20 mm; Length: 3875.27 mm; sets with these values: 2
BaseQuantities - Width: 45 mm; NetArea: 0.505584 m2; GrossArea: 0.174387 m2; CrossSectionArea: 0.0004 m2; NetVolume: 0.00348774 m3; GrossVolume: 0.00348774 m3
Name | Center of gravity Y (mm) | Center of gravity X (mm) | Part mark | Assembly mark
BRANNBESKYTTELSE | 43883.9 | 41399.6 | DIBB-0(?) | IBB-0(?)
BRANNBESKYTTELSE | 43947.7 | 41014.8 | DIBB-2(?) | IBB-2(?)

# IfcPlate: 50*2664, ISOLASJON
In: Undefined
Description: 50*2664; Material: MISCELLANEOUS/XPS
Aaj Tagger - Aaj_ObjektStatus: Nytt/ New; sets with these values: 2
Tekla Common - Center of gravity Z: 38998.3 mm; Center of gravity Y: 50115.9 mm; Center of gravity X: 55436.6 mm; Bottom elevation: +38.504; Top elevation: +39.469; Part mark: Concrete_IXPS-1-0(?); Assembly mark: IXPS-0(?); Phase: 1; Class: 912; Grade: XPS; Profile: 50*2664; Name: ISOLASJON; sets with these values: 2
Tekla Quantity - Net weight: 11.2925 kg; Gross weight: 12.1046 kg; Weight: 11.2925 kg; Net volume: 0.4517 m3; Gross volume: 0.49597 m3; Gross footprint area: 0 m2; Area per tons: 1652830587 m2; Net surface area: 18.6645 m2; Gross area: 9.68366 m2; Height: 2663.91 mm; Width: 50 mm; Length: 3635.14 mm; sets with these values: 2
BaseQuantities - Width: 2663.91 mm; NetArea: 18.6645 m2; GrossArea: 9.68366 m2; CrossSectionArea: 0.0025 m2; NetVolume: 0.451698 m3; GrossVolume: 0.495974 m3

# IfcPlate: 50*2751, ISOLASJON
In: Undefined
Description: 50*2751; Material: MISCELLANEOUS/XPS
Aaj Tagger - Aaj_ObjektStatus: Nytt/ New; sets with these values: 2
Tekla Common - Center of gravity Z: 39150.9 mm; Center of gravity Y: 44338.8 mm; Center of gravity X: 51372.9 mm; Bottom elevation: +38.524; Top elevation: +39.765; Part mark: Concrete_IXPS-1-0(?); Assembly mark: IXPS-0(?); Phase: 1; Class: 912; Grade: XPS; Profile: 50*2751; Name: ISOLASJON; sets with these values: 2
Tekla Quantity - Net weight: 36.6221 kg; Gross weight: 37.3509 kg; Weight: 36.6221 kg; Net volume: 1.46489 m3; Gross volume: 1.52558 m3; Gross footprint area: 0 m2; Area per tons: 1638544501 m2; Net surface area: 60.007 m2; Gross area: 29.8807 m2; Height: 2750.94 mm; Width: 50 mm; Length: 10862 mm; sets with these values: 2
BaseQuantities - Width: 2750.94 mm; NetArea: 60.007 m2; GrossArea: 29.8808 m2; CrossSectionArea: 0.0025 m2; NetVolume: 1.46489 m3; GrossVolume: 1.52558 m3

# IfcPlate: 50*2815, ISOLASJON
In: Undefined
Description: 50*2815; Material: MISCELLANEOUS/XPS
Aaj Tagger - Aaj_ObjektStatus: Nytt/ New; sets with these values: 2
Tekla Common - Center of gravity Z: 38967.4 mm; Center of gravity Y: 55806.1 mm; Center of gravity X: 41434.8 mm; Bottom elevation: +38.495; Top elevation: +39.462; Part mark: Concrete_IXPS-1-0(?); Assembly mark: IXPS-0(?); Phase: 1; Class: 912; Grade: XPS; Profile: 50*2815; Name: ISOLASJON; sets with these values: 2
Tekla Quantity - Net weight: 13.2849 kg; Gross weight: 14.3968 kg; Weight: 13.2849 kg; Net volume: 0.5314 m3; Gross volume: 0.57383 m3; Gross footprint area: 0 m2; Area per tons: 1649889881 m2; Net surface area: 21.9186 m2; Gross area: 11.5174 m2; Height: 2814.62 mm; Width: 50 mm; Length: 4092 mm; sets with these values: 2
BaseQuantities - Width: 2814.62 mm; NetArea: 21.9186 m2; GrossArea: 11.5174 m2; CrossSectionArea: 0.0025 m2; NetVolume: 0.531397 m3; GrossVolume: 0.573829 m3

# IfcPlate: 50*2953, ISOLASJON
In: Undefined
Description: 50*2953; Material: MISCELLANEOUS/XPS
Aaj Tagger - Aaj_ObjektStatus: Nytt/ New; sets with these values: 2
Tekla Common - Center of gravity Z: 39140.4 mm; Center of gravity Y: 50138 mm; Center of gravity X: 40505.7 mm; Bottom elevation: +38.493; Top elevation: +39.771; Part mark: Concrete_IXPS-1-0(?); Assembly mark: IXPS-0(?); Phase: 1; Class: 912; Grade: XPS; Profile: 50*2953; Name: ISOLASJON; sets with these values: 2
Tekla Quantity - Net weight: 28.1822 kg; Gross weight: 28.8608 kg; Weight: 28.1822 kg; Net volume: 1.12729 m3; Gross volume: 1.15528 m3; Gross footprint area: 0 m2; Area per tons: 1637058690 m2; Net surface area: 46.1359 m2; Gross area: 23.0887 m2; Height: 2952.85 mm; Width: 50 mm; Length: 7819.12 mm; sets with these values: 2
BaseQuantities - Width: 2952.85 mm; NetArea: 46.1359 m2; GrossArea: 23.0887 m2; CrossSectionArea: 0.0025 m2; NetVolume: 1.12729 m3; GrossVolume: 1.15528 m3

# IfcPlate: 50*3189 (2)
In: Undefined
Description: 50*3189
Aaj Tagger - Aaj_ObjektStatus: Nytt/ New; sets with these values: 2
Tekla Common - Center of gravity Y: 52168.4 mm; Center of gravity X: 51398.2 mm; Part mark: Concrete_IXPS-1-4(?); Phase: 1; Profile: 50*3189; sets with these values: 2
Tekla Quantity - Net volume: 0.86249 m3; Gross volume: 0.91221 m3; Gross footprint area: 0 m2; Net surface area: 35.5107 m2; Gross area: 19.3512 m2; Height: 3189.15 mm; Width: 200 mm; Length: 6067.82 mm; sets with these values: 2
BaseQuantities - Width: 3189.15 mm; NetArea: 35.5107 m2; GrossArea: 19.3512 m2; CrossSectionArea: 0.0025 m2; NetVolume: 0.862489 m3; GrossVolume: 0.912207 m3
Name | Material | Center of gravity Z (mm) | Bottom elevation | Top elevation | Assembly mark | Class | Grade | Name | Net weight (kg) = Weight (kg) | Gross weight (kg)
DRENSLAG | MISCELLANEOUS/Misc_Undefined | 39589 | +39.490 | +39.690 | IXPS-0(?) | 914 | Misc_Undefined | DRENSLAG | 0 | 0
ISOLASJON | MISCELLANEOUS/XPS | 39539 | +39.440 | +39.640 | IXPS-4(?) | 912 | XPS | ISOLASJON | 21.5622 | 24.189 | Tekla Quantity - Area per tons: 1646895566 m2

# IfcPlate: 50*3290 (2)
In: Undefined
Description: 50*3290
Aaj Tagger - Aaj_ObjektStatus: Nytt/ New; sets with these values: 2
Tekla Common - Center of gravity Y: 54323.2 mm; Center of gravity X: 46002.8 mm; Part mark: Concrete_IXPS-1-6(?); Phase: 1; Profile: 50*3290; sets with these values: 2
Tekla Quantity - Net volume: 0.92025 m3; Gross volume: 0.97198 m3; Gross footprint area: 0 m2; Net surface area: 37.8561 m2; Gross area: 20.8552 m2; Height: 3290.31 mm; Width: 200 mm; Length: 6338.36 mm; sets with these values: 2
BaseQuantities - Width: 3290.31 mm; NetArea: 37.8561 m2; GrossArea: 20.8552 m2; CrossSectionArea: 0.0025 m2; NetVolume: 0.920249 m3; GrossVolume: 0.971979 m3
Name | Material | Center of gravity Z (mm) | Bottom elevation | Top elevation | Assembly mark | Class | Grade | Name | Net weight (kg) = Weight (kg) | Gross weight (kg)
DRENSLAG | MISCELLANEOUS/Misc_Undefined | 39592 | +39.490 | +39.690 | IXPS-0(?) | 914 | Misc_Undefined | DRENSLAG | 0 | 0
ISOLASJON | MISCELLANEOUS/XPS | 39542 | +39.440 | +39.640 | IXPS-6(?) | 912 | XPS | ISOLASJON | 23.0062 | 26.069 | Tekla Quantity - Area per tons: 1645472278 m2

# IfcPlate: 50*5306 (2)
In: Undefined
Description: 50*5306
Aaj Tagger - Aaj_ObjektStatus: Nytt/ New; sets with these values: 2
Tekla Common - Center of gravity Y: 46364 mm; Center of gravity X: 48280 mm; Part mark: Concrete_IXPS-1-5(?); Assembly mark: IXPS-5(?); Phase: 1; Profile: 50*5306; sets with these values: 2
Tekla Quantity - Net volume: 2.78652 m3; Gross volume: 2.78652 m3; Gross footprint area: 0 m2; Net surface area: 85.0619 m2; Gross area: 56.9467 m2; Height: 5305.71 mm; Width: 200 mm; Length: 10733.1 mm; sets with these values: 2
BaseQuantities - Width: 5305.71 mm; NetArea: 85.0619 m2; GrossArea: 56.9467 m2; CrossSectionArea: 0.0025 m2; NetVolume: 2.78652 m3; GrossVolume: 2.78652 m3
Name | Material | Center of gravity Z (mm) | Bottom elevation | Top elevation | Class | Grade | Name | Net weight (kg) = Weight (kg) | Gross weight (kg)
DRENSLAG | MISCELLANEOUS/Misc_Undefined | 39890.5 | +39.790 | +39.990 | 914 | Misc_Undefined | DRENSLAG | 0 | 0
ISOLASJON | MISCELLANEOUS/XPS | 39840.5 | +39.740 | +39.940 | 912 | XPS | ISOLASJON | 69.6631 | 71.1834 | Tekla Quantity - Area per tons: 1221047452 m2

# IfcPlate: 50*5446 (2)
In: Undefined
Description: 50*5446
Aaj Tagger - Aaj_ObjektStatus: Nytt/ New; sets with these values: 2
Tekla Common - Center of gravity Y: 47730.4 mm; Center of gravity X: 44178.2 mm; Part mark: Concrete_IXPS-1-5(?); Assembly mark: IXPS-0(?); Phase: 1; Profile: 50*5446; sets with these values: 2
Tekla Quantity - Net volume: 2.44554 m3; Gross volume: 2.44554 m3; Gross footprint area: 0 m2; Net surface area: 99.4406 m2; Gross area: 63.5609 m2; Height: 5446.06 mm; Width: 200 mm; Length: 11671 mm; sets with these values: 2
BaseQuantities - Width: 5446.06 mm; NetArea: 99.4406 m2; GrossArea: 63.5609 m2; CrossSectionArea: 0.0025 m2; NetVolume: 2.44554 m3; GrossVolume: 2.44554 m3
Name | Material | Center of gravity Z (mm) | Bottom elevation | Top elevation | Class | Grade | Name | Net weight (kg) = Weight (kg) | Gross weight (kg)
DRENSLAG | MISCELLANEOUS/Misc_Undefined | 39882.8 | +39.790 | +39.990 | 914 | Misc_Undefined | DRENSLAG | 0 | 0
ISOLASJON | MISCELLANEOUS/XPS | 39832.8 | +39.740 | +39.940 | 912 | XPS | ISOLASJON | 61.1385 | 79.4511 | Tekla Quantity - Area per tons: 1626481633 m2

# IfcPlate: FIRKB167*200*100 (2)
In: Undefined
Description: FIRKB167*200*100; Material: CONCRETE/C35/45
Aaj Tagger - Aaj_ObjektStatus: Nytt/ New; sets with these values: 2
Tekla Common - Center of gravity Z: 39323.4 mm; Bottom elevation: +39.215; Top elevation: +39.415; Phase: 1; Class: 260; Grade: C35/45; Profile: FIRKB167*200*100; Name: PLASSTØPTDEKKE; sets with these values: 2
Tekla Quantity - Height: 167 mm; Width: 200 mm; sets with these values: 2
BaseQuantities - Width: 167 mm; CrossSectionArea: 0.0267 m2
Name | Center of gravity Y (mm) | Center of gravity X (mm) | Part mark | Assembly mark | Net weight (kg) = Gross weight (kg) = Weight (kg) | Net volume (m3) = Gross volume (m3) | Gross footprint area (m2) | Area per tons (m2) | Net surface area (m2) = Gross area (m2) = NetArea (m2) = GrossArea (m2) | Length (mm) | NetVolume (m3) = GrossVolume (m3)
PLASSTØPTDEKKE | 50829.2 | 54308 | Concrete_PLD-1-29(?) | PLD-15(?) | 214.93 | 0.08955 | 560736 | 10832192 | 2.32816 | 3377.4 | 0.089554
PLASSTØPTDEKKE | 55399 | 42857 | Concrete_PLD-1-31(?) | PLD-18(?) | 220.535 | 0.09189 | 574739 | 10821479 | 2.38651 | 3441.55 | 0.0918895

# IfcPlate: FIRKB192*200*100, PLASSTØPTDEKKE
In: Undefined
Description: FIRKB192*200*100; Material: CONCRETE/C35/45
Aaj Tagger - Aaj_ObjektStatus: Nytt/ New; sets with these values: 2
Tekla Common - Center of gravity Z: 39630.5 mm; Center of gravity Y: 49850.9 mm; Center of gravity X: 41919.7 mm; Bottom elevation: +39.520; Top elevation: +39.720; Part mark: Concrete_PLD-1-31(?); Assembly mark: PLD-18(?); Phase: 1; Class: 260; Grade: C35/45; Profile: FIRKB192*200*100; Name: PLASSTØPTDEKKE; sets with these values: 2
Tekla Quantity - Net weight: 547.698 kg; Gross weight: 547.698 kg; Weight: 547.698 kg; Net volume: 0.22821 m3; Gross volume: 0.22821 m3; Gross footprint area: 1500544 m2; Area per tons: 10268520 m2; Net surface area: 5.62405 m2; Gross area: 5.62405 m2; Height: 192 mm; Width: 200 mm; Length: 7815.33 mm; sets with these values: 2
BaseQuantities - Width: 192 mm; NetArea: 5.62405 m2; GrossArea: 5.62405 m2; CrossSectionArea: 0.0292 m2; NetVolume: 0.228208 m3; GrossVolume: 0.228208 m3

# IfcPlate: FIRKB197*200*100, PLASSTØPTDEKKE
In: Undefined
Description: FIRKB197*200*100; Material: CONCRETE/C35/45
Aaj Tagger - Aaj_ObjektStatus: Nytt/ New; sets with these values: 2
Tekla Common - Center of gravity Z: 39630.9 mm; Center of gravity Y: 45124.5 mm; Center of gravity X: 50270.5 mm; Bottom elevation: +39.520; Top elevation: +39.720; Part mark: Concrete_PLD-1-29(?); Assembly mark: PLD-15(?); Phase: 1; Class: 260; Grade: C35/45; Profile: FIRKB197*200*100; Name: PLASSTØPTDEKKE; sets with these values: 2
Tekla Quantity - Net weight: 765.936 kg; Gross weight: 765.936 kg; Weight: 765.936 kg; Net volume: 0.31914 m3; Gross volume: 0.31914 m3; Gross footprint area: 2116854 m2; Area per tons: 10168480 m2; Net surface area: 7.7884 m2; Gross area: 7.7884 m2; Height: 197 mm; Width: 200 mm; Length: 10745.5 mm; sets with these values: 2
BaseQuantities - Width: 197 mm; NetArea: 7.7884 m2; GrossArea: 7.7884 m2; CrossSectionArea: 0.0297 m2; NetVolume: 0.31914 m3; GrossVolume: 0.31914 m3

# IfcSlab: 150*10621, PLASSTØPTDEKKE
In: Undefined
Description: 150*10621; PredefinedType: FLOOR; Material: CONCRETE/C35/45
Aaj Tagger - Aaj_ObjektStatus: Eksisterende/ Existing; sets with these values: 2
Tekla Common - Center of gravity Z: 39425 mm; Center of gravity Y: 58040.6 mm; Center of gravity X: 50140.3 mm; Bottom elevation: +39.350; Top elevation: +39.500; Part mark: Concrete_PLD-1-1; Assembly mark: PLD-1; Phase: 1; Class: 260; Grade: C35/45; Profile: 150*10621; Name: PLASSTØPTDEKKE; sets with these values: 2
Tekla Quantity - Net weight: 21191.7 kg; Gross weight: 40502.1 kg; Weight: 21191.7 kg; Net volume: 8.82987 m3; Gross volume: 8.82987 m3; Gross footprint area: 58865807 m2; Area per tons: 5797984 m2; Net surface area: 122.869 m2; Gross area: 112.506 m2; Height: 10620.8 mm; Width: 150 mm; Length: 10592.9 mm; sets with these values: 2
BaseQuantities - Width: 150 mm; NetVolume: 8.82987 m3; NetArea: 58.8658 m2; NetWeight: 21191.7 kg

# IfcSlab: 150*5042, GULVPÅGRUNN
In: Undefined
Description: 150*5042; PredefinedType: FLOOR; Material: CONCRETE/C35/45
Aaj Tagger - Aaj_ObjektStatus: Eksisterende/ Existing; sets with these values: 2
Tekla Common - Center of gravity Z: 36925 mm; Center of gravity Y: 58670.7 mm; Center of gravity X: 50570.4 mm; Bottom elevation: +36.850; Top elevation: +37.000; Part mark: Concrete_GPG-1-2; Assembly mark: GPG-2; Phase: 1; Class: 263; Grade: C35/45; Profile: 150*5042; Name: GULVPÅGRUNN; sets with these values: 2
Tekla Quantity - Net weight: 14605.2 kg; Gross weight: 23906 kg; Weight: 14605.2 kg; Net volume: 6.08549 m3; Gross volume: 6.08549 m3; Gross footprint area: 40569965 m2; Area per tons: 5900218 m2; Net surface area: 86.1738 m2; Gross area: 66.4055 m2; Height: 5042.32 mm; Width: 150 mm; Length: 13169.6 mm; sets with these values: 2
BaseQuantities - Width: 150 mm; NetVolume: 6.08549 m3; NetArea: 40.57 m2; NetWeight: 14605.2 kg

# IfcSlab: 200*5000, GULVPÅGRUNN
In: Undefined
Description: 200*5000; PredefinedType: FLOOR; Material: CONCRETE/C45/55
Aaj Tagger - Aaj_ObjektStatus: Nytt/ New; sets with these values: 2
Tekla Common - Center of gravity Z: 37159.6 mm; Center of gravity Y: 44170 mm; Center of gravity X: 40059 mm; Bottom elevation: +36.850; Top elevation: +37.500; Part mark: Concrete_GPG-1-0(?); Assembly mark: GPG-0(?); Phase: 1; Class: 263; Grade: C45/55; Profile: 200*5000; Name: GULVPÅGRUNN; sets with these values: 2
Tekla Quantity - Net weight: 5764.98 kg; Gross weight: 8400.02 kg; Weight: 5764.98 kg; Net volume: 2.40208 m3; Gross volume: 5.68779 m3; Gross footprint area: 0 m2; Area per tons: 6570831 m2; Net surface area: 37.8807 m2; Gross area: 17.5 m2; Height: 5000 mm; Width: 650.33 mm; Length: 3500.01 mm; sets with these values: 2
BaseQuantities - Width: 650.33 mm; NetVolume: 2.40208 m3; NetArea: 0 m2; NetWeight: 5764.98 kg

# IfcSlab: 220*1659, PLASSTØPTDEKKE
In: Undefined
Description: 220*1659; PredefinedType: FLOOR; Material: CONCRETE/C35/45
Aaj Tagger - Aaj_ObjektStatus: Nytt/ New; sets with these values: 2
Tekla Common - Center of gravity Z: 38010.4 mm; Center of gravity Y: 41548.3 mm; Center of gravity X: 39428.4 mm; Bottom elevation: +37.900; Top elevation: +38.120; Part mark: Concrete_PLD-1-0(?); Assembly mark: PLD-0(?); Phase: 1; Class: 260; Grade: C35/45; Profile: 220*1659; Name: PLASSTØPTDEKKE; sets with these values: 2
Tekla Quantity - Net weight: 2088.44 kg; Gross weight: 2683.48 kg; Weight: 2088.44 kg; Net volume: 0.87018 m3; Gross volume: 1.04853 m3; Gross footprint area: 3955378 m2; Area per tons: 4667076 m2; Net surface area: 9.74691 m2; Gross area: 5.08235 m2; Height: 1658.67 mm; Width: 220 mm; Length: 3064.12 mm; sets with these values: 2
BaseQuantities - Width: 220 mm; NetVolume: 0.870183 m3; NetArea: 3.95538 m2; NetWeight: 2088.44 kg

# IfcSlab: 220*1890, PLASSTØPTDEKKE
In: Undefined
Description: 220*1890; PredefinedType: FLOOR; Material: CONCRETE/C35/45
Aaj Tagger - Aaj_ObjektStatus: Nytt/ New; sets with these values: 2
Tekla Common - Center of gravity Z: 38794.8 mm; Center of gravity Y: 40166.9 mm; Center of gravity X: 42569.8 mm; Bottom elevation: +38.300; Top elevation: +39.696; Part mark: Concrete_PLD-1-19(?); Assembly mark: PLD-15(?); Phase: 1; Class: 260; Grade: C35/45; Profile: 220*1890; Name: PLASSTØPTDEKKE; sets with these values: 2
Tekla Quantity - Net weight: 3313.59 kg; Gross weight: 6627.19 kg; Weight: 3313.59 kg; Net volume: 1.38066 m3; Gross volume: 1.38066 m3; Gross footprint area: 0 m2; Area per tons: 4773323 m2; Net surface area: 15.8169 m2; Gross area: 12.5515 m2; Height: 1890.45 mm; Width: 220 mm; Length: 6639.42 mm; sets with these values: 2
BaseQuantities - Width: 220 mm; NetVolume: 1.38066 m3; NetArea: 0 m2; NetWeight: 3313.59 kg

# IfcSlab: 220*2593, PLASSTØPTDEKKE
In: Undefined
Description: 220*2593; PredefinedType: FLOOR; Material: CONCRETE/C35/45
Aaj Tagger - Aaj_ObjektStatus: Nytt/ New; sets with these values: 2
Tekla Common - Center of gravity Z: 39212.3 mm; Center of gravity Y: 40283.2 mm; Center of gravity X: 44728.3 mm; Bottom elevation: +38.300; Top elevation: +39.718; Part mark: Concrete_PLD-1-26(?); Assembly mark: PLD-15(?); Phase: 1; Class: 260; Grade: C35/45; Profile: 220*2593; Name: PLASSTØPTDEKKE; sets with these values: 2
Tekla Quantity - Net weight: 4544.51 kg; Gross weight: 9089.02 kg; Weight: 4544.51 kg; Net volume: 1.89355 m3; Gross volume: 1.89355 m3; Gross footprint area: 0 m2; Area per tons: 4542914 m2; Net surface area: 20.6453 m2; Gross area: 17.2141 m2; Height: 2592.71 mm; Width: 220 mm; Length: 6639.42 mm; sets with these values: 2
BaseQuantities - Width: 220 mm; NetVolume: 1.89355 m3; NetArea: 0 m2; NetWeight: 4544.51 kg

# IfcSlab: 220*2730, PLASSTØPTDEKKE
In: Undefined
Description: 220*2730; PredefinedType: FLOOR; Material: CONCRETE/C35/45
Aaj Tagger - Aaj_ObjektStatus: Nytt/ New; sets with these values: 2
Tekla Common - Center of gravity Z: 38862.5 mm; Center of gravity Y: 50129.1 mm; Center of gravity X: 55417.7 mm; Bottom elevation: +38.274; Top elevation: +39.422; Part mark: Concrete_PLD-1-4(?); Assembly mark: PLD-15(?); Phase: 1; Class: 260; Grade: C35/45; Profile: 220*2730; Name: PLASSTØPTDEKKE; sets with these values: 2
Tekla Quantity - Net weight: 4854.19 kg; Gross weight: 5240.85 kg; Weight: 4854.19 kg; Net volume: 2.02258 m3; Gross volume: 2.18228 m3; Gross footprint area: 0 m2; Area per tons: 4324891 m2; Net surface area: 20.9939 m2; Gross area: 9.92586 m2; Height: 2730.47 mm; Width: 220 mm; Length: 3635.22 mm; sets with these values: 2
BaseQuantities - Width: 220 mm; NetVolume: 2.02258 m3; NetArea: 0 m2; NetWeight: 4854.19 kg

# IfcSlab: 220*2815, PLASSTØPTDEKKE
In: Undefined
Description: 220*2815; PredefinedType: FLOOR; Material: CONCRETE/C35/45
Aaj Tagger - Aaj_ObjektStatus: Nytt/ New; sets with these values: 2
Tekla Common - Center of gravity Z: 38839.9 mm; Center of gravity Y: 55794.2 mm; Center of gravity X: 41477.5 mm; Bottom elevation: +38.287; Top elevation: +39.415; Part mark: Concrete_PLD-1-0(?); Assembly mark: PLD-18(?); Phase: 1; Class: 260; Grade: C35/45; Profile: 220*2815; Name: PLASSTØPTDEKKE; sets with these values: 2
Tekla Quantity - Net weight: 5596.52 kg; Gross weight: 6081.2 kg; Weight: 5596.52 kg; Net volume: 2.33189 m3; Gross volume: 2.52485 m3; Gross footprint area: 0 m2; Area per tons: 4308251 m2; Net surface area: 24.1112 m2; Gross area: 11.5174 m2; Height: 2814.62 mm; Width: 220 mm; Length: 4092 mm; sets with these values: 2
BaseQuantities - Width: 220 mm; NetVolume: 2.33189 m3; NetArea: 0 m2; NetWeight: 5596.52 kg

# IfcSlab: 220*2845, PLASSTØPTDEKKE
In: Undefined
Description: 220*2845; PredefinedType: FLOOR; Material: CONCRETE/C35/45
Aaj Tagger - Aaj_ObjektStatus: Nytt/ New; sets with these values: 2
Tekla Common - Center of gravity Z: 39014.5 mm; Center of gravity Y: 44354.9 mm; Center of gravity X: 51348.2 mm; Bottom elevation: +38.285; Top elevation: +39.720; Part mark: Concrete_PLD-1-4(?); Assembly mark: PLD-15(?); Phase: 1; Class: 260; Grade: C35/45; Profile: 220*2845; Name: PLASSTØPTDEKKE; sets with these values: 2
Tekla Quantity - Net weight: 15841.5 kg; Gross weight: 16324.6 kg; Weight: 15841.5 kg; Net volume: 6.60064 m3; Gross volume: 6.71255 m3; Gross footprint area: 0 m2; Area per tons: 4176636 m2; Net surface area: 66.1643 m2; Gross area: 30.9179 m2; Height: 2845.26 mm; Width: 220 mm; Length: 10866.4 mm; sets with these values: 2
BaseQuantities - Width: 220 mm; NetVolume: 6.60064 m3; NetArea: 0 m2; NetWeight: 15841.5 kg

# IfcSlab: 220*2953, PLASSTØPTDEKKE
In: Undefined
Description: 220*2953; PredefinedType: FLOOR; Material: CONCRETE/C35/45
Aaj Tagger - Aaj_ObjektStatus: Nytt/ New; sets with these values: 2
Tekla Common - Center of gravity Z: 39016.3 mm; Center of gravity Y: 50119.6 mm; Center of gravity X: 40556.8 mm; Bottom elevation: +38.292; Top elevation: +39.726; Part mark: Concrete_PLD-1-5(?); Assembly mark: PLD-18(?); Phase: 1; Class: 260; Grade: C35/45; Profile: 220*2953; Name: PLASSTØPTDEKKE; sets with these values: 2
Tekla Quantity - Net weight: 11937.7 kg; Gross weight: 12191.2 kg; Weight: 11937.7 kg; Net volume: 4.97404 m3; Gross volume: 5.08323 m3; Gross footprint area: 0 m2; Area per tons: 4175106 m2; Net surface area: 49.8411 m2; Gross area: 23.0895 m2; Height: 2952.85 mm; Width: 220 mm; Length: 7819.39 mm; sets with these values: 2
BaseQuantities - Width: 220 mm; NetVolume: 4.97404 m3; NetArea: 0 m2; NetWeight: 11937.7 kg

# IfcSlab: 220*346, PLASSTØPTDEKKE
In: Undefined
Description: 220*346; PredefinedType: FLOOR; Material: CONCRETE/C35/45
Aaj Tagger - Aaj_ObjektStatus: Nytt/ New; sets with these values: 2
Tekla Common - Center of gravity Z: 38808.3 mm; Center of gravity Y: 38863.9 mm; Center of gravity X: 47739.7 mm; Bottom elevation: +38.300; Top elevation: +39.723; Part mark: Concrete_PLD-1-24(?); Assembly mark: PLD-15(?); Phase: 1; Class: 260; Grade: C35/45; Profile: 220*346; Name: PLASSTØPTDEKKE; sets with these values: 2
Tekla Quantity - Net weight: 291.889 kg; Gross weight: 583.778 kg; Weight: 291.889 kg; Net volume: 0.12162 m3; Gross volume: 0.12162 m3; Gross footprint area: 0 m2; Area per tons: 8860177 m2; Net surface area: 2.58619 m2; Gross area: 1.10564 m2; Height: 346.283 mm; Width: 220 mm; Length: 3192.88 mm; sets with these values: 2
BaseQuantities - Width: 220 mm; NetVolume: 0.12162 m3; NetArea: 0 m2; NetWeight: 291.889 kg

# IfcSlab: 220*483, PLASSTØPTDEKKE
In: Undefined
Description: 220*483; PredefinedType: FLOOR; Material: CONCRETE/C35/45
Aaj Tagger - Aaj_ObjektStatus: Nytt/ New; sets with these values: 2
Tekla Common - Center of gravity Z: 38808.1 mm; Center of gravity Y: 39080.6 mm; Center of gravity X: 47992.2 mm; Bottom elevation: +38.300; Top elevation: +39.723; Part mark: Concrete_PLD-1-23(?); Assembly mark: PLD-15(?); Phase: 1; Class: 260; Grade: C35/45; Profile: 220*483; Name: PLASSTØPTDEKKE; sets with these values: 2
Tekla Quantity - Net weight: 421.22 kg; Gross weight: 842.44 kg; Weight: 421.22 kg; Net volume: 0.17551 m3; Gross volume: 0.17551 m3; Gross footprint area: 0 m2; Area per tons: 7441551 m2; Net surface area: 3.13453 m2; Gross area: 1.59553 m2; Height: 483.374 mm; Width: 220 mm; Length: 3300.82 mm; sets with these values: 2
BaseQuantities - Width: 220 mm; NetVolume: 0.175508 m3; NetArea: 0 m2; NetWeight: 421.22 kg

# IfcSlab: 220*715, PLASSTØPTDEKKE
In: Undefined
Description: 220*715; PredefinedType: FLOOR; Material: CONCRETE/C35/45
Aaj Tagger - Aaj_ObjektStatus: Nytt/ New; sets with these values: 2
Tekla Common - Center of gravity Z: 38807.2 mm; Center of gravity Y: 38822.8 mm; Center of gravity X: 47361.7 mm; Bottom elevation: +38.300; Top elevation: +39.721; Part mark: Concrete_PLD-1-21(?); Assembly mark: PLD-15(?); Phase: 1; Class: 260; Grade: C35/45; Profile: 220*715; Name: PLASSTØPTDEKKE; sets with these values: 2
Tekla Quantity - Net weight: 602.424 kg; Gross weight: 1204.85 kg; Weight: 602.424 kg; Net volume: 0.25101 m3; Gross volume: 0.25101 m3; Gross footprint area: 0 m2; Area per tons: 6333957 m2; Net surface area: 3.81573 m2; Gross area: 2.28191 m2; Height: 714.688 mm; Width: 220 mm; Length: 3192.88 mm; sets with these values: 2
BaseQuantities - Width: 220 mm; NetVolume: 0.25101 m3; NetArea: 0 m2; NetWeight: 602.424 kg

# IfcSlab: 220*861, PLASSTØPTDEKKE
In: Undefined
Description: 220*861; PredefinedType: FLOOR; Material: CONCRETE/C35/45
Aaj Tagger - Aaj_ObjektStatus: Nytt/ New; sets with these values: 2
Tekla Common - Center of gravity Z: 38805.6 mm; Center of gravity Y: 38940 mm; Center of gravity X: 46802.1 mm; Bottom elevation: +38.300; Top elevation: +39.718; Part mark: Concrete_PLD-1-20(?); Assembly mark: PLD-15(?); Phase: 1; Class: 260; Grade: C35/45; Profile: 220*861; Name: PLASSTØPTDEKKE; sets with these values: 2
Tekla Quantity - Net weight: 686.114 kg; Gross weight: 1372.23 kg; Weight: 686.114 kg; Net volume: 0.28588 m3; Gross volume: 0.28588 m3; Gross footprint area: 0 m2; Area per tons: 5951723 m2; Net surface area: 4.08356 m2; Gross area: 2.59892 m2; Height: 861.019 mm; Width: 220 mm; Length: 3018.42 mm; sets with these values: 2
BaseQuantities - Width: 220 mm; NetVolume: 0.285881 m3; NetArea: 0 m2; NetWeight: 686.114 kg

# IfcSlab: 220*895, PLASSTØPTDEKKE
In: Undefined
Description: 220*895; PredefinedType: FLOOR; Material: CONCRETE/C35/45
Aaj Tagger - Aaj_ObjektStatus: Nytt/ New; sets with these values: 2
Tekla Common - Center of gravity Z: 38807.2 mm; Center of gravity Y: 39457.9 mm; Center of gravity X: 48306.3 mm; Bottom elevation: +38.300; Top elevation: +39.721; Part mark: Concrete_PLD-1-22(?); Assembly mark: PLD-15(?); Phase: 1; Class: 260; Grade: C35/45; Profile: 220*895; Name: PLASSTØPTDEKKE; sets with these values: 2
Tekla Quantity - Net weight: 753.268 kg; Gross weight: 1506.54 kg; Weight: 753.268 kg; Net volume: 0.31386 m3; Gross volume: 0.31386 m3; Gross footprint area: 0 m2; Area per tons: 5875985 m2; Net surface area: 4.42619 m2; Gross area: 2.85329 m2; Height: 894.764 mm; Width: 220 mm; Length: 3188.87 mm; sets with these values: 2
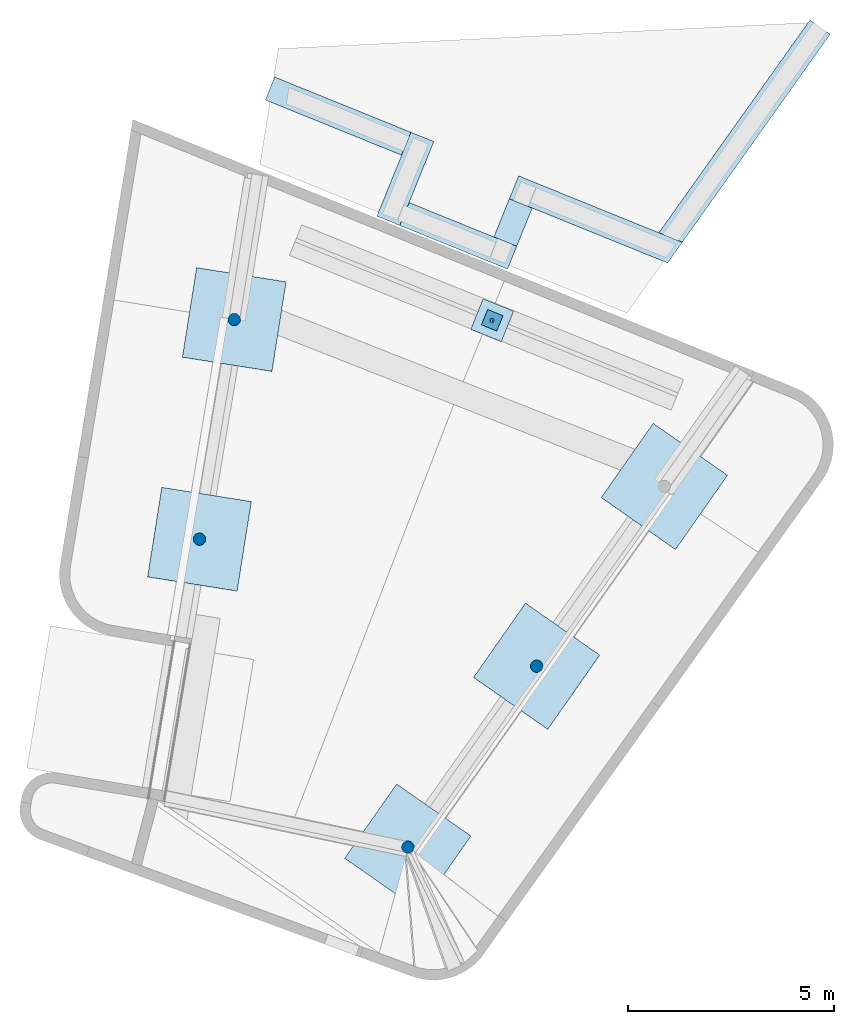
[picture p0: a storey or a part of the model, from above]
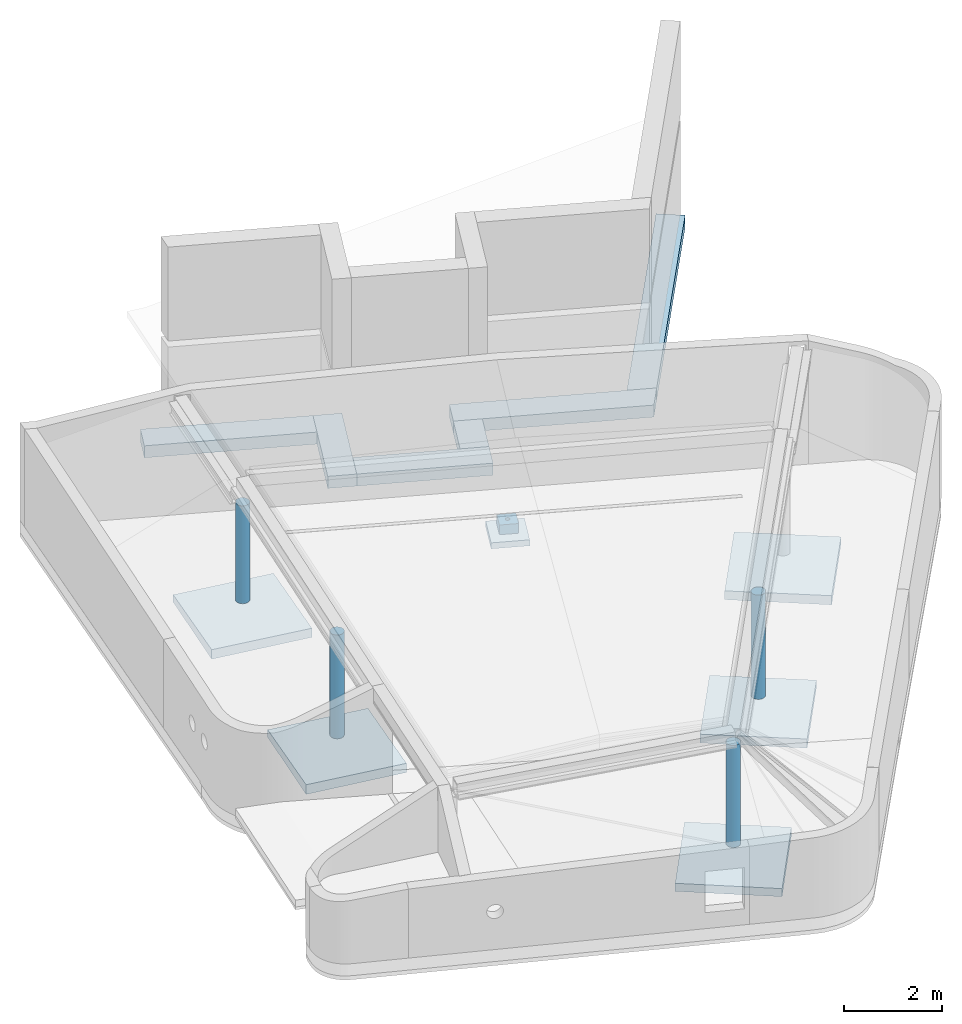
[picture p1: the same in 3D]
Properties of the parts of a building model (IFC2X3), part 2 of 2

# IfcSlab: 220*895, PLASSTØPTDEKKE
BaseQuantities - Width: 220 mm; NetVolume: 0.313862 m3; NetArea: 0 m2; NetWeight: 753.268 kg

# IfcSlab: 220*99, PLASSTØPTDEKKE
In: Undefined
Description: 220*99; PredefinedType: FLOOR; Material: CONCRETE/C35/45
Aaj Tagger - Aaj_ObjektStatus: Nytt/ New; sets with these values: 2
Tekla Common - Center of gravity Z: 39204.6 mm; Center of gravity Y: 39866.9 mm; Center of gravity X: 47467.8 mm; Bottom elevation: +38.300; Top elevation: +39.702; Part mark: Concrete_PLD-1-25(?); Assembly mark: PLD-15(?); Phase: 1; Class: 260; Grade: C35/45; Profile: 220*99; Name: PLASSTØPTDEKKE; sets with these values: 2
Tekla Quantity - Net weight: 86.502 kg; Gross weight: 173.004 kg; Weight: 86.502 kg; Net volume: 0.03604 m3; Gross volume: 0.03604 m3; Gross footprint area: 0 m2; Area per tons: 20677202 m2; Net surface area: 1.78862 m2; Gross area: 0.32766 m2; Height: 99.266 mm; Width: 220 mm; Length: 3300.82 mm; sets with these values: 2
BaseQuantities - Width: 220 mm; NetVolume: 0.0360425 m3; NetArea: 0 m2; NetWeight: 86.5021 kg

# IfcSlab: 300*10545, PLASSTØPTFUNDAMENT
In: Undefined
Description: 300*10545; PredefinedType: FLOOR; Material: CONCRETE/C45/55
Aaj Tagger - Aaj_ObjektStatus: Nytt/ New; sets with these values: 2
Tekla Common - Center of gravity Z: 36542.7 mm; Center of gravity Y: 50305.6 mm; Center of gravity X: 47349 mm; Bottom elevation: +36.250; Top elevation: +36.850; Part mark: Concrete_PLF-1-0(?); Assembly mark: PLF-0(?); Phase: 1; Class: 210; Grade: C45/55; Profile: 300*10545; Name: PLASSTØPTFUNDAMENT; sets with these values: 2
Tekla Quantity - Net weight: 124334 kg; Gross weight: 142995 kg; Weight: 124334 kg; Net volume: 51.806 m3; Gross volume: 52.014 m3; Gross footprint area: 0 m2; Area per tons: 2945367 m2; Net surface area: 366.211 m2; Gross area: 198.604 m2; Height: 10545.4 mm; Width: 600 mm; Length: 18833.2 mm; sets with these values: 2
BaseQuantities - Width: 600 mm; NetVolume: 51.806 m3; NetArea: 0 m2; NetWeight: 124334 kg

# IfcSlab: 300*6761, PLASSTØPTFUNDAMENT
In: Undefined
Description: 300*6761; PredefinedType: FLOOR; Material: CONCRETE/C45/55
Aaj Tagger - Aaj_ObjektStatus: Nytt/ New; sets with these values: 2
Tekla Common - Center of gravity Z: 36700 mm; Center of gravity Y: 42210.3 mm; Center of gravity X: 44637.3 mm; Bottom elevation: +36.550; Top elevation: +36.850; Part mark: Concrete_PLF-1-0(?); Assembly mark: PLF-0(?); Phase: 1; Class: 210; Grade: C45/55; Profile: 300*6761; Name: PLASSTØPTFUNDAMENT; sets with these values: 2
Tekla Quantity - Net weight: 52294 kg; Gross weight: 70020.5 kg; Weight: 52294 kg; Net volume: 21.7892 m3; Gross volume: 21.7892 m3; Gross footprint area: 72630608 m2; Area per tons: 3025982 m2; Net surface area: 158.241 m2; Gross area: 97.2508 m2; Height: 6761.21 mm; Width: 300 mm; Length: 14383.6 mm; sets with these values: 2
BaseQuantities - Width: 300 mm; NetVolume: 21.7892 m3; NetArea: 72.6306 m2; NetWeight: 52294 kg

# IfcSlab: 320*10636, HULLDEKKE
In: Undefined
Description: 320*10636; PredefinedType: FLOOR; Material: CONCRETE/C45/55
Aaj Tagger - Aaj_ObjektStatus: Nytt/ New; sets with these values: 2
Tekla Common - Center of gravity Z: 39580 mm; Center of gravity Y: 47159.3 mm; Center of gravity X: 46096.5 mm; Bottom elevation: +39.420; Top elevation: +39.740; Part mark: Concrete_PD-1-4; Assembly mark: PD-4; Phase: 1; Class: 162; Grade: C45/55; Profile: 320*10636; Name: HULLDEKKE; sets with these values: 2
Tekla Quantity - Net weight: 69668.9 kg; Gross weight: 96252.5 kg; Weight: 69668.9 kg; Net volume: 29.0287 m3; Gross volume: 29.0287 m3; Gross footprint area: 90714750 m2; Area per tons: 2783538 m2; Net surface area: 193.926 m2; Gross area: 125.329 m2; Height: 10636.2 mm; Width: 320 mm; Length: 11783.2 mm; sets with these values: 2
BaseQuantities - Width: 320 mm; NetVolume: 29.0287 m3; NetArea: 90.7147 m2; NetWeight: 69668.9 kg

# IfcSlab: 320*3291, HULLDEKKE
In: Undefined
Description: 320*3291; PredefinedType: FLOOR; Material: CONCRETE/C45/55
Aaj Tagger - Aaj_ObjektStatus: Nytt/ New; sets with these values: 2
Tekla Common - Center of gravity Z: 39280 mm; Center of gravity Y: 53198.5 mm; Center of gravity X: 48581.8 mm; Bottom elevation: +39.120; Top elevation: +39.440; Part mark: Concrete_PD-1-3; Assembly mark: PD-3; Phase: 1; Class: 162; Grade: C45/55; Profile: 320*3291; Name: HULLDEKKE; sets with these values: 2
Tekla Quantity - Net weight: 28949 kg; Gross weight: 31322.8 kg; Weight: 28949 kg; Net volume: 12.0621 m3; Gross volume: 12.0621 m3; Gross footprint area: 37693982 m2; Area per tons: 2934950 m2; Net surface area: 84.9638 m2; Gross area: 40.7849 m2; Height: 3290.56 mm; Width: 320 mm; Length: 12394.5 mm; sets with these values: 2
BaseQuantities - Width: 320 mm; NetVolume: 12.0621 m3; NetArea: 37.694 m2; NetWeight: 28949 kg

# IfcSlab: 75*3184, PÅSTØP
In: Undefined
Description: 75*3184; PredefinedType: FLOOR; Material: CONCRETE/C30/37
Aaj Tagger - Aaj_ObjektStatus: Nytt/ New; sets with these values: 2
Tekla Common - Center of gravity Z: 39489.8 mm; Center of gravity Y: 52546.4 mm; Center of gravity X: 50514.4 mm; Bottom elevation: +39.440; Top elevation: +39.590; Part mark: Concrete_PST-1-3(?); Assembly mark: PST-3(?); Phase: 1; Class: 262; Grade: C30/37; Profile: 75*3184; Name: PÅSTØP; sets with these values: 2
Tekla Quantity - Net weight: 2985.8 kg; Gross weight: 3431.67 kg; Weight: 2985.8 kg; Net volume: 1.24408 m3; Gross volume: 1.33747 m3; Gross footprint area: 0 m2; Area per tons: 11747154 m2; Net surface area: 35.0747 m2; Gross area: 19.0648 m2; Height: 3184.05 mm; Width: 150.33 mm; Length: 5987.61 mm; sets with these values: 2
BaseQuantities - Width: 150.33 mm; NetVolume: 1.24408 m3; NetArea: 0 m2; NetWeight: 2985.8 kg

# IfcSlab: 75*3290, PÅSTØP
In: Undefined
Description: 75*3290; PredefinedType: FLOOR; Material: CONCRETE/C30/37
Aaj Tagger - Aaj_ObjektStatus: Nytt/ New; sets with these values: 2
Tekla Common - Center of gravity Z: 39489.6 mm; Center of gravity Y: 53968.2 mm; Center of gravity X: 46953.1 mm; Bottom elevation: +39.440; Top elevation: +39.590; Part mark: Concrete_PST-1-2(?); Assembly mark: PST-2(?); Phase: 1; Class: 262; Grade: C30/37; Profile: 75*3290; Name: PÅSTØP; sets with these values: 2
Tekla Quantity - Net weight: 3177.29 kg; Gross weight: 3718.8 kg; Weight: 3177.29 kg; Net volume: 1.32387 m3; Gross volume: 1.42199 m3; Gross footprint area: 0 m2; Area per tons: 11794414 m2; Net surface area: 37.4743 m2; Gross area: 20.66 m2; Height: 3290.1 mm; Width: 150.33 mm; Length: 6279.44 mm; sets with these values: 2
BaseQuantities - Width: 150.33 mm; NetVolume: 1.32387 m3; NetArea: 0 m2; NetWeight: 3177.29 kg

# IfcSlab: 75*5308, PÅSTØP
In: Undefined
Description: 75*5308; PredefinedType: FLOOR; Material: CONCRETE/C30/37
Aaj Tagger - Aaj_ObjektStatus: Nytt/ New; sets with these values: 2
Tekla Common - Center of gravity Z: 39792.6 mm; Center of gravity Y: 46626 mm; Center of gravity X: 47754.6 mm; Bottom elevation: +39.740; Top elevation: +39.890; Part mark: Concrete_PST-1-1(?); Assembly mark: PST-1(?); Phase: 1; Class: 262; Grade: C30/37; Profile: 75*5308; Name: PÅSTØP; sets with these values: 2
Tekla Quantity - Net weight: 8450.77 kg; Gross weight: 10254.7 kg; Weight: 8450.77 kg; Net volume: 3.52115 m3; Gross volume: 3.52115 m3; Gross footprint area: 0 m2; Area per tons: 10155871 m2; Net surface area: 85.8249 m2; Gross area: 56.9707 m2; Height: 5307.94 mm; Width: 150.33 mm; Length: 10733.1 mm; sets with these values: 2
BaseQuantities - Width: 150.33 mm; NetVolume: 3.52115 m3; NetArea: 0 m2; NetWeight: 8450.77 kg

# IfcSlab: 75*5446, PÅSTØP
In: Undefined
Description: 75*5446; PredefinedType: FLOOR; Material: CONCRETE/C30/37
Aaj Tagger - Aaj_ObjektStatus: Nytt/ New; sets with these values: 2
Tekla Common - Center of gravity Z: 39787.2 mm; Center of gravity Y: 47532.7 mm; Center of gravity X: 44960.1 mm; Bottom elevation: +39.740; Top elevation: +39.890; Part mark: Concrete_PST-1-1(?); Assembly mark: PST-0(?); Phase: 1; Class: 262; Grade: C30/37; Profile: 75*5446; Name: PÅSTØP; sets with these values: 2
Tekla Quantity - Net weight: 7980.53 kg; Gross weight: 11441 kg; Weight: 7980.53 kg; Net volume: 3.32522 m3; Gross volume: 3.32522 m3; Gross footprint area: 0 m2; Area per tons: 12547094 m2; Net surface area: 100.132 m2; Gross area: 63.5614 m2; Height: 5446.06 mm; Width: 150.33 mm; Length: 11671.1 mm; sets with these values: 2
BaseQuantities - Width: 150.33 mm; NetVolume: 3.32522 m3; NetArea: 0 m2; NetWeight: 7980.53 kg

# IfcWall: 1800*250, PLASSTØPTYTTERVEGG
In: Undefined
Description: 1800*250; Material: CONCRETE/C45/55
Aaj Tagger - Aaj_ObjektStatus: Nytt/ New; sets with these values: 2
Tekla Common - Center of gravity Z: 38705.1 mm; Center of gravity Y: 41375.1 mm; Center of gravity X: 40650.6 mm; Bottom elevation: +38.116; Top elevation: +39.766; Part mark: Concrete_PLYV-1-0(?); Assembly mark: PLYV-0(?); Phase: 1; Class: 251; Grade: C45/55; Profile: 1800*250; Name: PLASSTØPTYTTERVEGG; sets with these values: 2
Tekla Quantity - Net weight: 1057.95 kg; Gross weight: 1623.84 kg; Weight: 1057.95 kg; Net volume: 0.44081 m3; Gross volume: 0.73811 m3; Gross footprint area: 0 m2; Area per tons: 4702359 m2; Net surface area: 4.97487 m2; Gross area: 7.62497 m2; Height: 1650 mm; Width: 250 mm; Length: 1640.24 mm; sets with these values: 2
BaseQuantities - Length: 1640.24 mm; OuterSurfaceArea: 4.97487 m2; NetVolume: 0.440813 m3; NetWeight: 1057.95 kg

# IfcWall: 2100*250, PLASSTØPTYTTERVEGG
In: Undefined
Description: 2100*250; Material: CONCRETE/C45/55
Aaj Tagger - Aaj_ObjektStatus: Nytt/ New; sets with these values: 2
Tekla Common - Center of gravity Z: 37653.8 mm; Center of gravity Y: 41185.5 mm; Center of gravity X: 38311.7 mm; Bottom elevation: +36.850; Top elevation: +38.575; Part mark: Concrete_PLYV-1-9(?); Assembly mark: PLYV-1(?); Phase: 1; Class: 251; Grade: C45/55; Profile: 2100*250; Name: PLASSTØPTYTTERVEGG; sets with these values: 2
Tekla Quantity - Net weight: 2053.82 kg; Gross weight: 2030.12 kg; Weight: 2053.82 kg; Net volume: 0.85576 m3; Gross volume: 1.11976 m3; Gross footprint area: 0 m2; Area per tons: 4251575 m2; Net surface area: 8.73197 m2; Gross area: 11.0789 m2; Height: 1725 mm; Width: 250 mm; Length: 1961.48 mm; sets with these values: 2
BaseQuantities - Length: 1961.48 mm; OuterSurfaceArea: 8.73197 m2; NetVolume: 0.855758 m3; NetWeight: 2053.82 kg

# IfcWall: 2250*250, PLASSTØPTYTTERVEGG
In: Undefined
Description: 2250*250; Material: CONCRETE/C45/55
Aaj Tagger - Aaj_ObjektStatus: Nytt/ New; sets with these values: 2
Tekla Common - Center of gravity Z: 37918.4 mm; Center of gravity Y: 41736.8 mm; Center of gravity X: 51162.5 mm; Bottom elevation: +36.774; Top elevation: +39.000; Part mark: Concrete_PLYV-1-18(?); Assembly mark: PLYV-1(?); Phase: 1; Class: 251; Grade: C45/55; Profile: 2250*250; Name: PLASSTØPTYTTERVEGG; sets with these values: 2
Tekla Quantity - Net weight: 8292.14 kg; Gross weight: 8534.98 kg; Weight: 8292.14 kg; Net volume: 3.45506 m3; Gross volume: 3.59395 m3; Gross footprint area: 1597310 m2; Area per tons: 3850577 m2; Net surface area: 31.9295 m2; Gross area: 33.0712 m2; Height: 2226.39 mm; Width: 250 mm; Length: 6389.24 mm; sets with these values: 2
BaseQuantities - Length: 6389.24 mm; OuterSurfaceArea: 31.9295 m2; NetVolume: 3.45506 m3; NetWeight: 8292.14 kg

# IfcWall: 2350*400 (12)
In: Undefined
Description: 2350*400; Material: CONCRETE/C35/45
Tekla Common - Assembly mark: PLV-1; Phase: 1; Class: 250; Grade: C35/45; Profile: 2350*400; Name: PLASSTØPTVEGG; sets with these values: 2
Tekla Quantity - Height: 2350 mm; Width: 400 mm; sets with these values: 2
Aaj Tagger - Aaj_ObjektStatus: Eksisterende/ Existing; sets with these values: 2
Name | Center of gravity Z (mm) | Center of gravity Y (mm) | Center of gravity X (mm) | Bottom elevation | Top elevation | Part mark | Net weight (kg) = Weight (kg) = NetWeight (kg) | Gross weight (kg) | Net volume (m3) = Gross volume (m3) = NetVolume (m3) | Gross footprint area (m2) | Area per tons (m2) | Net surface area (m2) = Gross area (m2) = OuterSurfaceArea (m2) | Tekla Quantity, Length (mm) = BaseQuantities, Length (mm)
PLASSTØPTVEGG | 40675 | 58170.2 | 55159.9 | +39.500 | +41.850 | Concrete_PLV-1-5 | 14367.5 | 14474.2 | 5.98645 | 2547425 | 2570600 | 36.933 | 6415.87
PLASSTØPTVEGG | 38175 | 58503.2 | 45563.7 | +37.000 | +39.350 | Concrete_PLV-1-3 | 7247.44 | 7352.23 | 3.01977 | 1285007 | 2700798 | 19.5739 | 3258.97
PLASSTØPTVEGG | 38175 | 58170.2 | 55159.9 | +37.000 | +39.350 | Concrete_PLV-1-5 | 14367.5 | 14474.2 | 5.98645 | 2547425 | 2570600 | 36.933 | 6415.87
PLASSTØPTVEGG | 40675 | 55810.6 | 47943.5 | +39.500 | +41.850 | Concrete_PLV-1-4 | 5459.96 | 5459.96 | 2.27498 | 968078 | 2782268 | 15.1911 | 2420.19
PLASSTØPTVEGG | 38175 | 55810.6 | 47943.5 | +37.000 | +39.350 | Concrete_PLV-1-4 | 5459.96 | 5459.96 | 2.27498 | 968078 | 2782268 | 15.1911 | 2420.19
PLASSTØPTVEGG | 38175 | 56022.9 | 49551 | +37.000 | +39.350 | Concrete_PLV-1-2 | 4512 | 4512 | 1.88 | 800000 | 2854610 | 12.88 | 2000
PLASSTØPTVEGG | 38175 | 57081.2 | 46936.9 | +37.000 | +39.350 | Concrete_PLV-1-2 | 4512 | 4512 | 1.88 | 800000 | 2854610 | 12.88 | 2000
PLASSTØPTVEGG | 40675 | 58503.2 | 45563.7 | +39.500 | +41.850 | Concrete_PLV-1-3 | 7247.44 | 7352.23 | 3.01977 | 1285007 | 2700798 | 19.5739 | 3258.97
PLASSTØPTVEGG | 40675 | 56022.9 | 49551 | +39.500 | +41.850 | Concrete_PLV-1-2 | 4512 | 4512 | 1.88 | 800000 | 2854610 | 12.88 | 2000
PLASSTØPTVEGG | 40675 | 57081.2 | 46936.9 | +39.500 | +41.850 | Concrete_PLV-1-2 | 4512 | 4512 | 1.88 | 800000 | 2854610 | 12.88 | 2000
PLASSTØPTVEGG | 38175 | 56010.2 | 51712.4 | +37.000 | +39.350 | Concrete_PLV-1-1 | 8157.66 | 8264.39 | 3.39903 | 1446394 | 2671582 | 21.7939 | 3663.3
PLASSTØPTVEGG | 40675 | 56010.2 | 51712.4 | +39.500 | +41.850 | Concrete_PLV-1-1 | 8157.66 | 8264.39 | 3.39903 | 1446394 | 2671582 | 21.7939 | 3663.3

# IfcWall: 2400*250, PLASSTØPTYTTERVEGG
In: Undefined
Description: 2400*250; Material: CONCRETE/C45/55
Aaj Tagger - Aaj_ObjektStatus: Nytt/ New; sets with these values: 2
Tekla Common - Center of gravity Z: 37770.2 mm; Center of gravity Y: 39572.2 mm; Center of gravity X: 42438.8 mm; Bottom elevation: +36.850; Top elevation: +38.801; Part mark: Concrete_PLYV-1-17(?); Assembly mark: PLYV-1(?); Phase: 1; Class: 251; Grade: C45/55; Profile: 2400*250; Name: PLASSTØPTYTTERVEGG; sets with these values: 2
Tekla Quantity - Net weight: 7247.87 kg; Gross weight: 8291.42 kg; Weight: 7247.87 kg; Net volume: 3.01995 m3; Gross volume: 4.25078 m3; Gross footprint area: 0 m2; Area per tons: 4114472 m2; Net surface area: 29.8212 m2; Gross area: 38.7486 m2; Height: 1950.56 mm; Width: 250 mm; Length: 7084.64 mm; sets with these values: 2
BaseQuantities - Length: 7084.64 mm; OuterSurfaceArea: 29.8212 m2; NetVolume: 3.01995 m3; NetWeight: 7247.87 kg

# IfcWall: 2500*250, PLASSTØPTYTTERVEGG
In: Undefined
Description: 2500*250; Material: CONCRETE/C45/55
Aaj Tagger - Aaj_ObjektStatus: Nytt/ New; sets with these values: 2
Tekla Common - Center of gravity Z: 37871.8 mm; Center of gravity Y: 38163.8 mm; Center of gravity X: 47775.5 mm; Bottom elevation: +36.850; Top elevation: +39.000; Part mark: Concrete_PLYV-1-6(?); Assembly mark: PLYV-1(?); Phase: 1; Class: 251; Grade: C45/55; Profile: 2500*250; Name: PLASSTØPTYTTERVEGG; sets with these values: 2
Tekla Quantity - Net weight: 5031.17 kg; Gross weight: 5089.07 kg; Weight: 5031.17 kg; Net volume: 2.09632 m3; Gross volume: 2.56658 m3; Gross footprint area: 0 m2; Area per tons: 3946289 m2; Net surface area: 19.8545 m2; Gross area: 23.8418 m2; Height: 2150 mm; Width: 250.821 mm; Length: 3945.01 mm; sets with these values: 2
BaseQuantities - Length: 3945.01 mm; OuterSurfaceArea: 19.8545 m2; NetVolume: 2.09632 m3; NetWeight: 5031.17 kg

# IfcWall: 2800*250 (2)
In: Undefined
Description: 2800*250; Material: CONCRETE/C45/55
Aaj Tagger - Aaj_ObjektStatus: Nytt/ New; sets with these values: 2
Tekla Common - Top elevation: +39.000; Assembly mark: PLYV-1(?); Phase: 1; Class: 251; Grade: C45/55; Profile: 2800*250; Name: PLASSTØPTYTTERVEGG; sets with these values: 2
Tekla Quantity - Width: 250 mm; sets with these values: 2
Name | Center of gravity Z (mm) | Center of gravity Y (mm) | Center of gravity X (mm) | Bottom elevation | Part mark | Net weight (kg) = Weight (kg) = NetWeight (kg) | Gross weight (kg) | Net volume (m3) = NetVolume (m3) | Gross volume (m3) | Gross footprint area (m2) | Area per tons (m2) | Net surface area (m2) = OuterSurfaceArea (m2) | Gross area (m2) | Height (mm) | Tekla Quantity, Length (mm) = BaseQuantities, Length (mm)
PLASSTØPTYTTERVEGG | 37834.9 | 54336.2 | 39768.5 | +36.557 | Concrete_PLYV-1-16(?) | 11177.5 | 11768.6 | 4.65727 | 5.60062 | 2000221 | 3796865 | 42.4393 | 50.2233 | 2442.83 | 8029.34
PLASSTØPTYTTERVEGG | 37830 | 46962.8 | 54900.5 | +36.550 | Concrete_PLYV-1-8(?) | 8963.56 | 9392.19 | 3.73482 | 4.47247 | 1597310 | 3820273 | 34.2432 | 40.3744 | 2450 | 6389.24

# IfcWall: 3240*250, PLASSTØPTYTTERVEGG
In: Undefined
Description: 3240*250; Material: CONCRETE/C45/55
Aaj Tagger - Aaj_ObjektStatus: Nytt/ New; sets with these values: 2
Tekla Common - Center of gravity Z: 38086.5 mm; Center of gravity Y: 55272.6 mm; Center of gravity X: 48008 mm; Bottom elevation: +36.550; Top elevation: +39.790; Part mark: Concrete_PLYV-1-5(?); Assembly mark: PLYV-1(?); Phase: 1; Class: 251; Grade: C45/55; Profile: 3240*250; Name: PLASSTØPTYTTERVEGG; sets with these values: 2
Tekla Quantity - Net weight: 29792.7 kg; Gross weight: 31638 kg; Weight: 29792.7 kg; Net volume: 12.4136 m3; Gross volume: 13.1595 m3; Gross footprint area: 0 m2; Area per tons: 3680053 m2; Net surface area: 109.639 m2; Gross area: 115.04 m2; Height: 3240 mm; Width: 250.353 mm; Length: 16274.7 mm; sets with these values: 2
BaseQuantities - Length: 16274.7 mm; OuterSurfaceArea: 109.639 m2; NetVolume: 12.4136 m3; NetWeight: 29792.7 kg

# IfcWall: 3500*250 (2)
In: Undefined
Description: 3500*250; Material: CONCRETE/C45/55
Aaj Tagger - Aaj_ObjektStatus: Nytt/ New; sets with these values: 2
Tekla Common - Assembly mark: PLYV-1(?); Phase: 1; Class: 251; Grade: C45/55; Profile: 3500*250; Name: PLASSTØPTYTTERVEGG; sets with these values: 2
Tekla Quantity - Gross footprint area: 0 m2; sets with these values: 2
Name | Center of gravity Z (mm) | Center of gravity Y (mm) | Center of gravity X (mm) | Bottom elevation | Top elevation | Part mark | Net weight (kg) = Weight (kg) = NetWeight (kg) | Gross weight (kg) | Net volume (m3) = NetVolume (m3) | Gross volume (m3) | Area per tons (m2) | Net surface area (m2) = OuterSurfaceArea (m2) | Gross area (m2) | Height (mm) | Width (mm) | Tekla Quantity, Length (mm) = BaseQuantities, Length (mm)
PLASSTØPTYTTERVEGG | 37970.4 | 42310 | 39494.9 | +36.850 | +39.761 | Concrete_PLYV-1-13(?) | 4853.18 | 6234.23 | 2.02216 | 3.29397 | 3968169 | 19.2582 | 29.9923 | 2910.67 | 250.195 | 3569.76
PLASSTØPTYTTERVEGG | 38002.3 | 47310.5 | 39565.6 | +36.787 | +39.765 | Concrete_PLYV-1-10(?) | 9391.2 | 11735.6 | 3.913 | 5.91683 | 3892148 | 36.5519 | 52.4753 | 2977.99 | 250.483 | 6567.99

# IfcWall: 3710*250, PLASSTØPTYTTERVEGG
In: Undefined
Description: 3710*250; Material: CONCRETE/C45/55
Aaj Tagger - Aaj_ObjektStatus: Nytt/ New; sets with these values: 2
Tekla Common - Center of gravity Z: 37855.3 mm; Center of gravity Y: 51194.3 mm; Center of gravity X: 56616 mm; Bottom elevation: +36.550; Top elevation: +39.640; Part mark: Concrete_PLYV-1-12(?); Assembly mark: PLYV-1(?); Phase: 1; Class: 251; Grade: C45/55; Profile: 3710*250; Name: PLASSTØPTYTTERVEGG; sets with these values: 2
Tekla Quantity - Net weight: 6092.89 kg; Gross weight: 6841.33 kg; Weight: 6092.89 kg; Net volume: 2.53871 m3; Gross volume: 3.62967 m3; Gross footprint area: 0 m2; Area per tons: 3887828 m2; Net surface area: 23.6881 m2; Gross area: 32.861 m2; Height: 3090 mm; Width: 250.7 mm; Length: 3690.04 mm; sets with these values: 2
BaseQuantities - Length: 3690.04 mm; OuterSurfaceArea: 23.6881 m2; NetVolume: 2.53871 m3; NetWeight: 6092.89 kg
